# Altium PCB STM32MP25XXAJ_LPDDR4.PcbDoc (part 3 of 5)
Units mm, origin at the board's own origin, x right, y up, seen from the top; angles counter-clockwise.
Board outline 172 x 137 mm, 4 copper layers (Top Layer, Signal Layer 1, Signal Layer 2, Bottom Layer), stack 1.614 mm thick; 188 components, 294 nets, 1141 pads, 872 vias.
Unrouted connection lines stored in the file: 13.

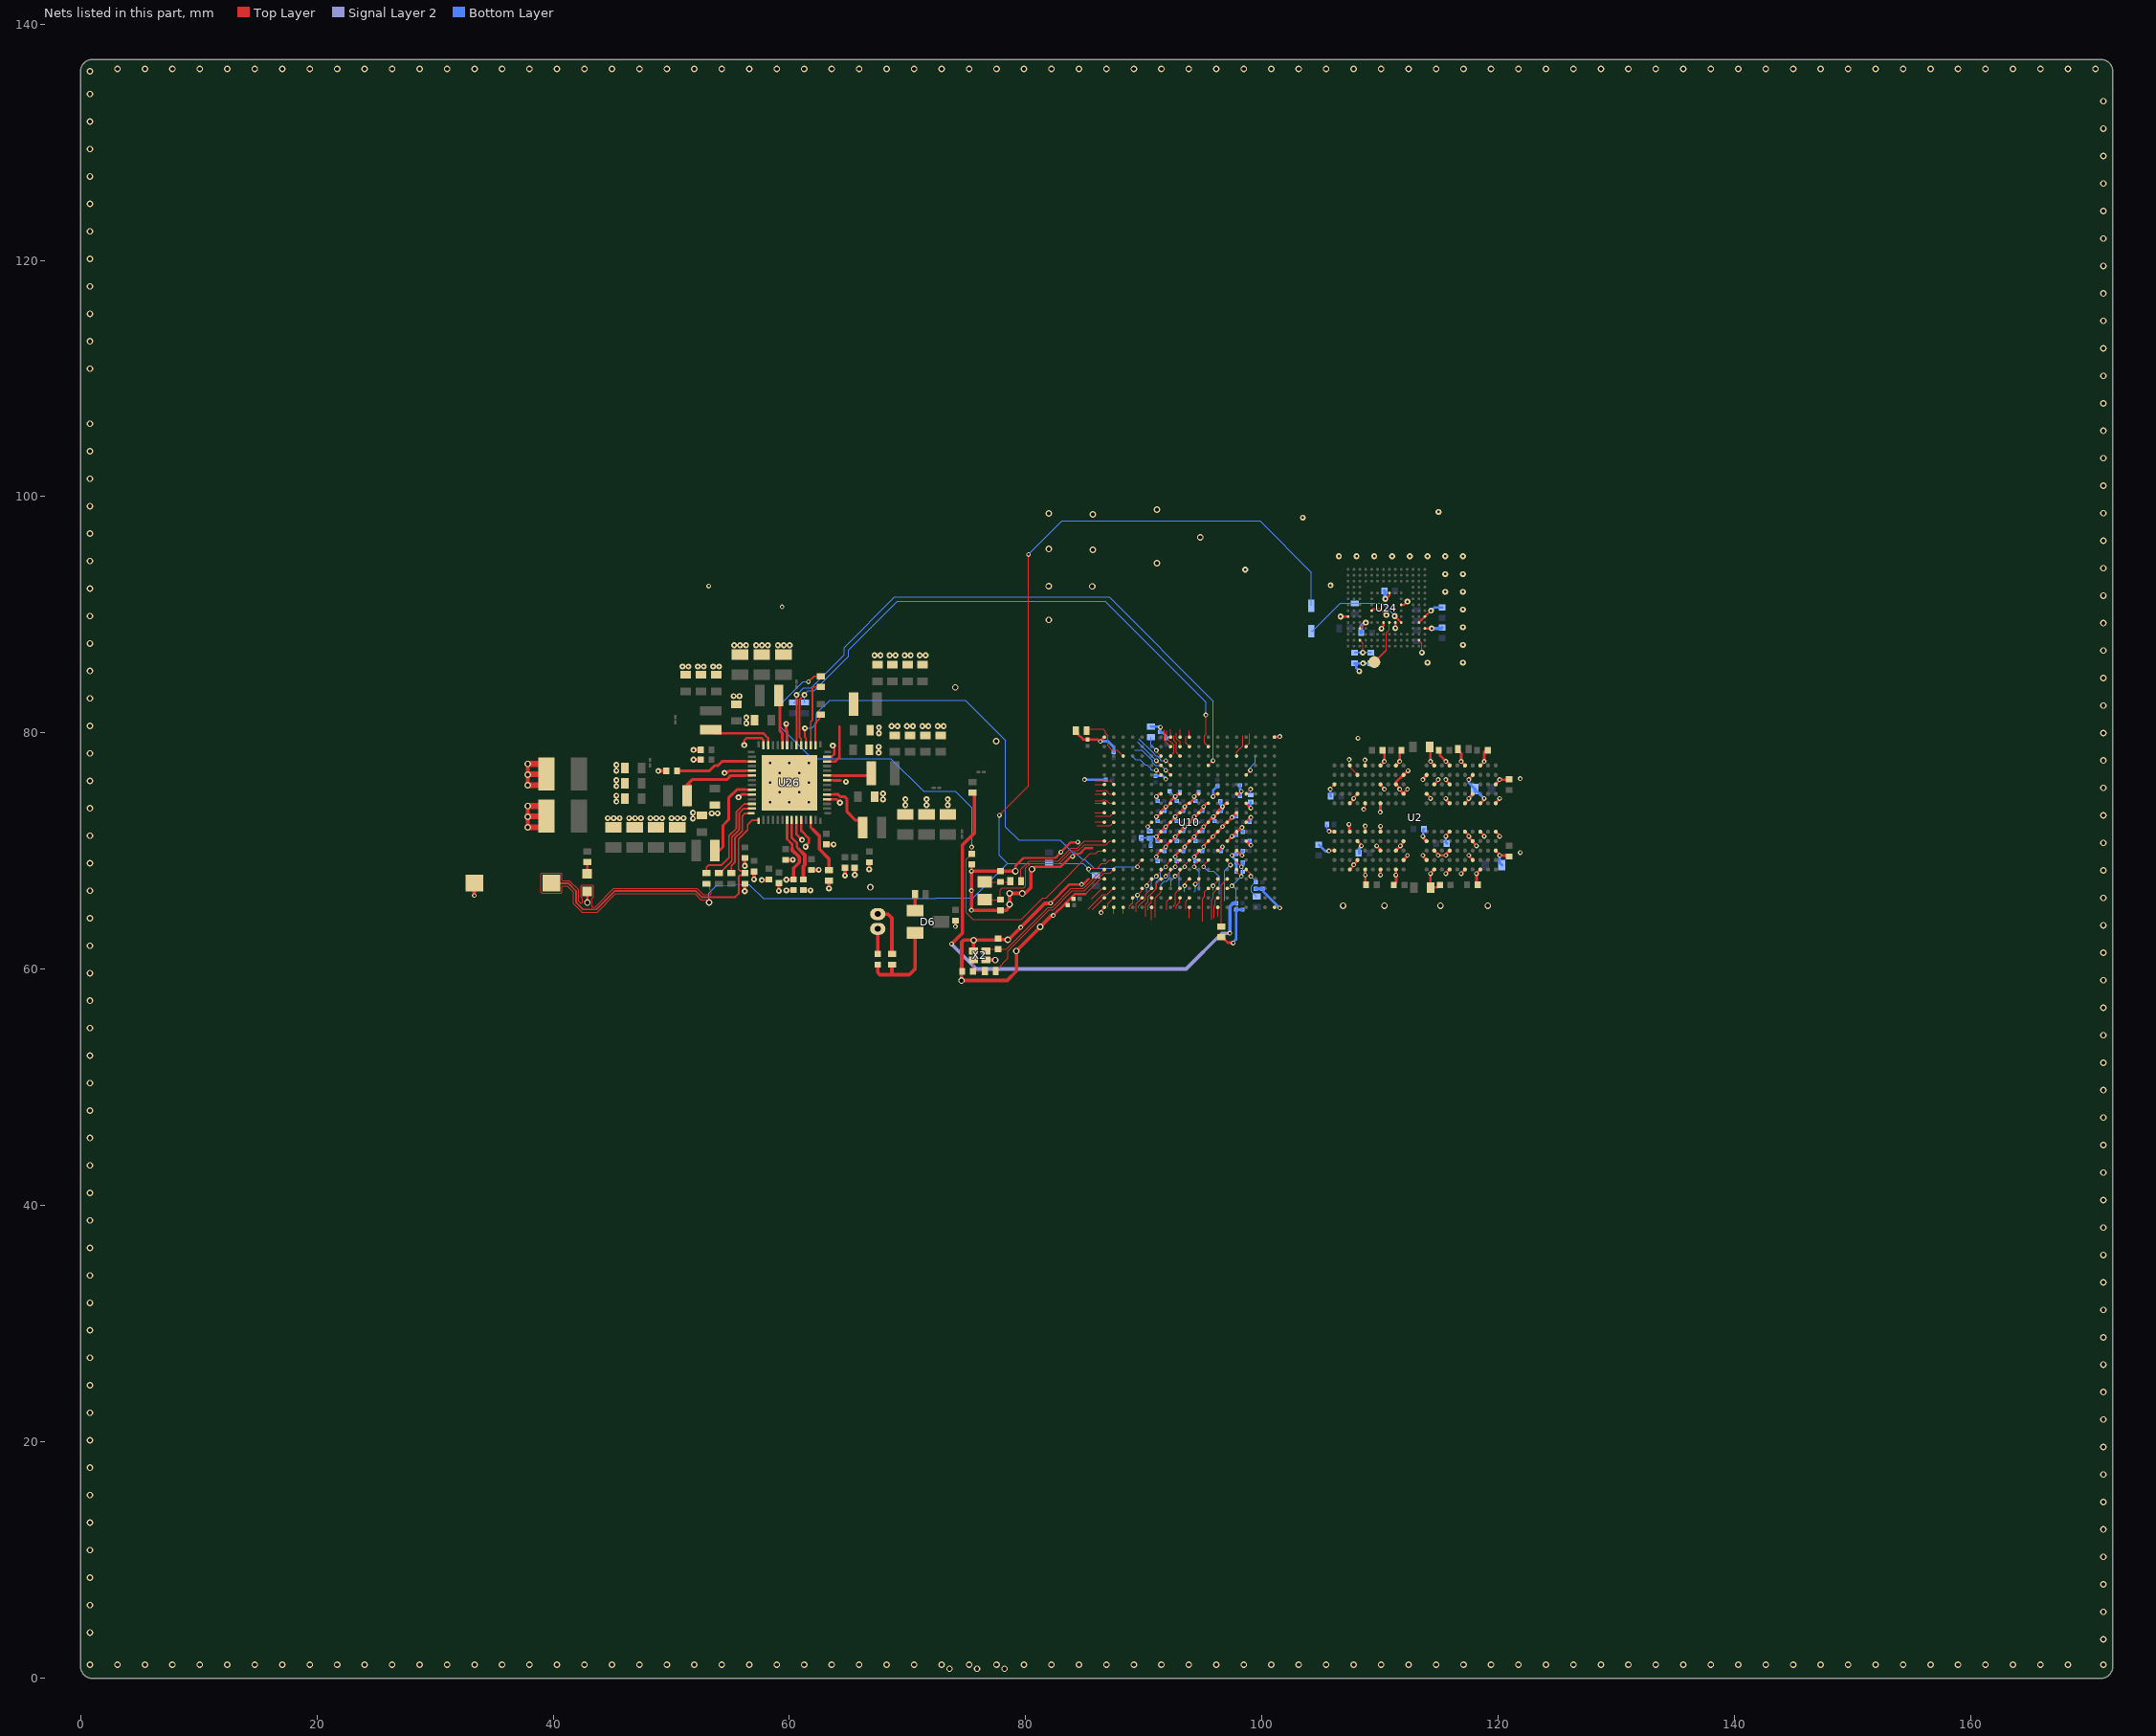
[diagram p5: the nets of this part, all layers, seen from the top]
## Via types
v1: diameter 0.55, hole 0.35, Top Layer to Bottom Layer, 349 vias
v2: diameter 0.4, hole 0.2, Top Layer to Bottom Layer, tented both sides, 257 vias
v3: diameter 0.5, hole 0.2, Top Layer to Bottom Layer, 189 vias
v4: diameter 0.4, hole 0.2, Top Layer to Bottom Layer, 77 vias

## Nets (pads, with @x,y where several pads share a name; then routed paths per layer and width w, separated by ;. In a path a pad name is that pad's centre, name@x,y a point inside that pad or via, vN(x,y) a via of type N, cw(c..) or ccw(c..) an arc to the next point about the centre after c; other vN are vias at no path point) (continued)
GND: B2.1 C18.2 C19.1 C20.1 C21.1 C22.1 C23.1 C24.1 C26.1 C27.1 C28.1 C29.1 C30.1 C32.1 C33.1 C34.1 C35.1 C36.1 C37.1 C38.1 C39.1 C40.1 C41.1 C42.2 C43.1 C50.1 C51.1 C52.1 C53.2 C54.2 C55.2 C56.2 C57.2 C58.2 C59.2 C60.2 C61.2 C62.1 C63.1 C64.1 C65.1 C66.1 C67.1 C68.1 C79.1 C81.2 C86.2 C87.1 C90.1 C91.2 C92.2 C141.2 C142.2 C143.1 C152.1 C153.1 C154.1 C155.1 C156.1 C157.1 C159.1 C161.1 C163.1 C164.2 C165.1 C166.1 C167.1 C168.1 C169.1 C171.1 C173.2 C174.2 C175.1 C176.1 C177.1 C180.1 C182.1 C183.1 C184.1 C186.1 C187.1 C188.1 C189.1 C190.2 C191.2 C192.1 C193.1 C195.1 C196.1 C199.1 C200.1 C201.1 C202.1 C204.1 C206.1 C207.1 C208.2 C209.1 C210.1 C217.2 C267.1 C342.1 C344.1 C352.1 C353.1 C354.1 C355.1 C356.1 C357.1 C360.2 C372.1 C377.1 C378.1 C380.1 C381.1 C382.1 C383.1 C384.1 C386.1 C387.2 C388.1 C389.2 C390.1 C393.1 C399.2 C400.1 C402.1 C404.1 C406.1 C407.1 C408.1 C409.1 C417.1 C478.1 C479.1 C481.1 LD11.2 R26.1 R57.1 R112.1 R161.2 R162.2 R196.1 U2.A3 U2.A10 U2.AB3 U2.AB5 U2.AB8 U2.AB10 U2.C1 U2.C5 U2.C8 U2.C12 U2.D2 U2.D4 U2.D9 U2.D11 U2.E1 U2.E5 U2.E8 U2.E12 U2.G1 U2.G3 U2.G5 U2.G8 U2.G10 U2.G12 U2.J1 U2.J3 U2.J10 U2.J12 U2.K2 U2.K4 U2.K9 U2.K11 U2.N2 U2.N4 U2.N9 U2.N11 U2.P1 U2.P3 U2.P10 U2.P12 U2.T1 U2.T3 U2.T5 U2.T8 U2.T10 U2.T12 U2.V1 U2.V5 U2.V8 U2.V12 U2.W2 U2.W4 U2.W9 U2.W11 U2.Y1 U2.Y5 U2.Y8 U2.Y12 U10.A1 U10.A19 U10.G7 U10.G9 U10.G11 U10.G13 U10.G15 U10.H8 U10.H10 U10.H12 U10.H14 U10.H16 U10.J7 U10.J9 U10.J11 U10.J13 U10.J15 U10.K8 U10.K10 U10.K12 U10.K14 U10.K16 U10.L7 U10.L9 U10.L11 U10.L13 U10.L15 U10.M7 U10.M8 U10.M10 U10.M12 U10.M14 U10.M16 U10.N7 U10.N9 U10.N11 U10.N13 U10.N15 U10.T1 U10.W1 U10.W19 U24.A6 U24.C4 U24.E7 U24.G5 U24.H10 U24.J5 U24.K8 U24.N2 U24.N5 U24.P4 U24.P6 U26.9 U26.10 U26.18 U26.22 U26.27 U26.36 U26.41 U26.47 U26.52 U26.57 X2.2 X2.4 | length 247.7
  Top Layer w0.09: U10.W19@101.05,65.25 101.45,65.25 v4@101.5,65.2 ; v4@105.778,75.296 106.157,75.675 U2.A10@106.175,75.675 ; v4(107.375,77.75) 107.375,77.375 U2.C12@107.45,77.3 ; U2.C12@107.421,77.247 107.474,77.194 107.474,77.051 U2.D11@108.075,76.45 ; v4@108.6,73.525 108.725,73.65 U2.E8@108.725,74.05 ; v4@108.7,77.75 108.725,77.725 U2.E12@108.725,77.25 ; U24.N2@113.275,87.85 113.525,87.6 v3(113.525,86.8)
  Top Layer w0.1: v3@44.624,72.799 v3@44.625,72.8 ; X2.2@75.547,61.575 X2.2@75.548,61.576 ; v1@75.573,62.448 v1(75.587,62.462) v1@75.6,62.475 ; 85.068,66.382 86.336,67.65 U10.T1@86.65,67.65
  Top Layer w0.11: v4@86.291,64.884 U10.W1@86.65,65.244
  Top Layer w0.18: v3(106.65,89.85) U24.A6@107.275,89.85 ; U24.C4@108.275,88.85 108.725,89.3 108.735,89.3 v3(108.775,89.34) ; U24.E7@109.275,90.35 109.283,90.35 109.416,90.483 110.028,90.483 110.516,89.995 v3(110.525,89.995) ; v3(110.1,88.825) 110.1,88.913 110.275,89.088 U24.G5@110.275,89.35 ; v3@110.425,91.275 110.775,91.625 U24.H10@110.775,91.85 ; v3(111.275,88.875) 111.285,88.885 111.285,89.34 U24.J5@111.275,89.35 ; U24.K8@111.775,90.85 112.025,90.85 v3(112.3,91.125) ; U24.N5@113.275,89.35 U24.P6@113.775,89.85 114.275,90.35 v3(114.3,90.35) ; U24.P4@113.775,88.85 v3(114.35,88.85)
  Top Layer w0.2: v1(42.887,65.648) LD11.2@42.887,66.577 ; U26.27@63.17,78 63.579,78 63.77,78.191 63.77,78.91 v3@63.816,78.956 ; v3(63.67,78.93) v3@63.727,78.873 ; C87.1@74.05,64.125 74.05,63.634 v2(74.051,63.633) ; v2(75.402,68.305) 75.416,68.319 C33.1@75.416,68.915 ; v1(79.125,68.3) 79.125,68.75 79.8,69.425 82.507,69.425 82.975,69.893 v2(82.975,69.925) 83.8,70.75 v4@84.456,70.75 ; v1(80.525,68.475) 80.599,68.475 80.818,68.693 82.956,68.693 83.784,69.522 v2@83.934,69.522 ; v2(82.1,65.6) 83.683,67.182 84.711,67.182 84.763,67.234 84.911,67.234 85.319,67.643 ; v2(82.325,64.55) 83.363,65.587 ; C67.1@83.55,65.425 83.525,65.425 83.363,65.587 ; v2@83.975,69.575 84.19,69.79 84.568,69.79 85.031,70.253 85.603,70.253 ; C406.1@84.025,65.975 83.9,66.1 C406.1@83.9,66.125 ; 85.068,66.382 85.065,66.385 84.784,66.385 84.781,66.382 84.158,66.382 C406.1@83.9,66.125 ; v4(91.05,69.525) 91.05,69.65 U10.N7@91.45,70.05 ; U10.N7@91.445,70.05 U10.N7@91.45,70.05 ; v2@91.85,70.438 91.462,70.05 U10.N7@91.45,70.05 ; v2@91.851,70.438 v2@91.863,70.438 ; v2(92.65,69.525) 92.709,69.584 92.709,69.709 U10.N9@93.05,70.05 93.125,70.05 v2(93.45,70.375) ; U2.G10@110.025,75.65 110.025,75.61 110.1,75.535 110.1,75.531 110.35,75.281 v2(110.35,75.25) ; 83.363,65.587 C406.1@83.9,66.125
  Top Layer w0.21: v3(56.175,78.975) 56.175,79.375 56.38,79.58 57.609,79.58 57.8,79.389 U26.41@57.8,78.97 ; 56.275,74.8 U26.52@56.83,74.8 ; 56.275,76.8 U26.47@56.83,76.8 ; U26.36@59.8,78.97 59.8,79.525 ; U26.9@60.6,72.63 60.6,71.42 v3(61.068,70.952) ; U26.10@61,72.63 61,71.734 61.635,71.099 61.635,70.72 61.37,70.456 v3(61.37,70.377) ; U26.18@63.17,74.4 63.972,74.4 v3(64.272,74.1) ; U26.22@63.17,76 63.725,76
  Top Layer w0.22: R162.2@84.25,80.2 84.395,80.055 84.395,79.914 84.854,79.455 85.22,79.455 C353.1@85.225,79.45 86.097,79.45 86.262,79.285 v4(86.31,79.285) 86.31,79.298 86.63,79.618 86.63,79.648 U10.A1@86.625,79.653 ; v2(91.05,71.225) 91.05,71.25 U10.L7@91.45,71.65 91.45,71.675 v2(91.85,72.075) ; v2(91.05,72.925) 91.084,72.959 91.164,72.959 U10.J7@91.45,73.245 ; v2@91.052,74.625 91.257,74.831 91.431,74.831 U10.G7@91.45,74.85 ; v2@91.07,71.146 91.112,71.146 91.393,70.865 91.393,70.85 U10.M7@91.445,70.85 ; U10.J7@91.45,73.25 91.465,73.265 91.465,73.404 v2@91.836,73.775 ; v2(91.85,70.375) 91.85,70.438 91.85,70.45 U10.M8@92.25,70.85 ; v2(91.85,73.775) 91.884,73.809 91.999,73.809 92.239,74.05 U10.H8@92.25,74.05 92.25,74.225 v2(92.65,74.625) 92.65,74.645 92.841,74.836 93.031,74.836 U10.G9@93.045,74.85 ; v2@91.875,72.075 U10.K8@92.25,72.45 92.65,72.85 v2(92.65,72.925) 92.65,72.939 92.894,73.183 92.926,73.183 92.993,73.25 U10.J9@93.05,73.25 93.425,73.625 v2@93.425,73.775 ; U10.M8@92.245,70.85 U10.M8@92.25,70.85 ; v4(92.65,71.225) 93.05,71.625 U10.L9@93.05,71.65 ; v4@92.698,71.18 92.637,71.18 92.307,70.85 U10.M8@92.25,70.85 ; U10.L9@93.045,71.65 93.348,71.954 93.441,71.954 93.441,72.046 U10.J11@94.647,73.253 ; v2(93.45,70.375) 93.45,70.45 U10.M10@93.85,70.85 93.875,70.85 v2(94.25,71.225) ; v2(93.45,73.775) 93.45,73.787 93.676,74.013 93.813,74.013 U10.H10@93.85,74.05 94.25,74.45 v2(94.25,74.625) 94.457,74.832 94.626,74.832 U10.G11@94.645,74.85 ; v2@94.225,69.525 94.65,69.95 U10.N11@94.65,70.05 ; v2@94.25,71.255 94.645,71.65 U10.L11@94.65,71.65 ; U10.J11@94.625,73.25 95.05,73.675 v2(95.05,73.775) 95.05,73.793 95.267,74.01 95.41,74.01 U10.H12@95.45,74.05 ; U10.L11@94.675,71.7 v4(95.05,72.075) ; v4(95.05,70.375) 95.084,70.409 95.084,70.484 U10.M12@95.45,70.85 95.825,71.225 v4(95.85,71.225) 95.85,71.253 U10.L13@96.247,71.65 ; v4@95.075,72.075 U10.K12@95.45,72.45 95.465,72.465 95.465,72.535 95.845,72.915 95.909,72.915 U10.J13@96.245,73.25 ; v2(95.85,74.625) 95.85,74.638 96.05,74.838 96.238,74.838 U10.G13@96.25,74.85 ; U10.N13@96.246,70.05 96.325,70.05 v2(96.65,70.375) ; U10.L13@96.25,71.661 v4@96.65,72.061 ; U10.J13@96.25,73.25 96.25,73.375 v2(96.65,73.775) ; R196.1@96.55,62.725 96.645,62.725 97.111,62.259 97.516,62.259 v4(97.55,62.225) ; v4(96.65,72.075) 97.025,72.45 U10.K14@97.05,72.45 ; v2@96.65,73.781 96.878,74.01 97.01,74.01 U10.H14@97.05,74.05 ; U10.M14@97.052,70.85 v2@97.45,71.248 ; U10.K14@97.052,72.45 v4@97.45,72.848 ; v4@97.45,72.854 U10.J15@97.846,73.25 ; v2@97.484,71.284 U10.L15@97.85,71.65 97.9,71.65 v2@98.25,72 ; U10.N15@97.835,70.035 U10.N15@97.85,70.05 ; U10.N15@97.85,70.049 v4@98.249,69.65 ; U10.G15@97.85,74.85 98.04,74.85 v2(98.25,75.06) ; U10.K16@98.65,72.45 v2(99.05,72.85) ; U10.H16@98.65,74.05 v2(99.05,73.65) ; U10.M16@98.652,70.85 99.002,70.5 v2(99.05,70.5) ; U10.A19@101.05,79.65 101.065,79.665 101.53,79.665 v4@101.55,79.685 ; v2(105.65,70.015) 105.699,70.015 105.734,70.05 U2.A3@106.125,70.05 ; v2(107.345,72.275) 107.375,72.245 107.375,71.861 107.4,71.836 107.4,71.675 U2.C5@107.425,71.65 ; U2.C1@107.425,68.45 107.75,68.776 v2(107.75,68.85) 108.075,69.175 U2.D2@108.075,69.25 ; U2.C8@107.425,74.05 107.745,74.37 107.75,74.37 107.784,74.405 107.784,74.56 U2.D9@108.075,74.85 ; v2@107.725,68.825 v2@107.725,68.901 ; U2.D4@108.075,70.85 108.365,70.56 108.365,70.47 v2@108.4,70.435 ; C66.1@108.725,67.295 C66.1@108.85,67.17 ; v2@108.725,67.95 U2.E1@108.725,68.45 ; U2.E5@108.725,71.65 v2(108.725,72.125) v2@108.725,72.135 ; v2(108.736,67.975) 108.736,67.314 C66.1@108.9,67.15 ; v2(109.7,70.45) 109.96,70.19 109.96,70.15 110.025,70.085 U2.G3@110.025,70.05 ; v2@110.025,67.96 v2(110.025,67.97) U2.G1@110.025,68.45 ; U2.G5@110.025,71.65 v4@110.025,72.075 ; U2.G12@110.025,77.25 110.35,77.575 v2(110.35,77.6) 110.35,78.251 110.337,78.264 110.337,78.405 C64.1@110.192,78.55 ; C54.2@111.15,67.135 111.15,67.16 111.353,67.364 111.353,67.941 v2(111.325,67.97) U2.J1@111.325,68.45 ; U2.J3@111.325,70.05 111.7,70.426 v2(111.7,70.45) 111.7,70.478 111.95,70.728 U2.K4@111.95,70.825 ; U2.J10@111.325,75.645 111.659,75.31 v2@111.659,75.295 ; U2.J10@111.325,75.65 111.349,75.675 111.349,75.849 111.95,76.45 U2.K11@111.975,76.45 112.324,76.8 v2(112.35,76.8) ; U2.J12@111.325,77.25 111.33,77.25 v2@111.65,77.57 ; v2(111.65,77.6) 111.65,78.251 111.655,78.256 111.655,78.405 C52.1@111.8,78.55 ; v2@111.694,75.276 111.684,75.266 111.684,75.164 U2.K9@111.975,74.873 ; U2.K2@111.975,69.25 111.98,69.25 v2@112.3,69.57 ; U2.K9@111.975,74.85 U2.K9@111.975,74.873 ; v2(112.3,75.25) 112.3,75.208 111.975,74.883 U2.K9@111.975,74.873 ; v2(113.6,69.65) 113.634,69.616 113.634,69.561 U2.N2@113.925,69.271 ; v2@113.6,71.17 113.92,70.85 U2.N4@113.925,70.85 ; v2@113.6,76.12 113.925,76.445 U2.N11@113.925,76.45 ; U2.N9@113.925,74.85 114.215,74.56 114.215,74.485 v2(114.25,74.45) ; C62.1@114.045,78.625 114.2,78.78 114.25,78.73 v2(114.25,77.6) 114.25,77.575 U2.P12@114.575,77.25 ; C63.1@114.25,66.92 v2(114.25,68.1) 114.25,68.12 114.575,68.445 U2.P1@114.575,68.45 ; C63.1@114.25,66.938 114.853,66.938 114.88,66.965 114.905,66.965 115.05,67.11 C267.1@115.05,67.135 ; U2.P3@114.575,70.035 114.865,69.745 114.865,69.685 v2(114.9,69.65) v2(115.55,69.65) ; U2.P10@114.575,75.65 114.895,75.97 v2@114.9,75.97 ; C65.1@114.975,78.56 115.063,78.472 115.063,78.087 v2(115.55,77.6) 115.875,77.275 U2.T12@115.875,77.25 ; v2@115.55,68.12 115.875,68.445 U2.T1@115.875,68.45 ; v2@115.55,71.32 115.875,71.645 U2.T5@115.875,71.65 ; v2(115.55,74.45) 115.584,74.416 115.584,74.341 U2.T8@115.875,74.05 ; v2@115.55,75.97 115.87,75.65 U2.T10@115.875,75.65 ; v2@115.575,69.625 v2(115.55,69.65) ; U2.T3@115.875,70.05 115.875,70.024 115.584,69.734 115.584,69.685 v2(115.55,69.65) ; R26.1@116.575,78.635 116.575,78.54 R26.1@116.72,78.395 ; R26.1@116.721,78.395 116.85,78.266 v2(116.85,77.6) ; v2@116.85,68.12 117.175,68.445 U2.V1@117.175,68.45 ; v2@116.85,77.575 U2.V12@117.175,77.25 ; U2.V5@117.175,71.65 117.465,71.36 117.465,71.205 117.5,71.17 117.505,71.17 U2.W4@117.825,70.85 117.825,70.815 117.89,70.75 117.89,70.71 v2(118.15,70.45) ; U2.V8@117.175,74.05 117.465,74.341 117.465,74.416 v2(117.5,74.45) 117.5,74.525 U2.W9@117.825,74.85 ; v2(117.5,69.65) 117.5,69.603 117.825,69.278 U2.W2@117.825,69.25 ; v2@117.5,76.12 117.825,76.445 U2.W11@117.825,76.45 ; C55.2@118.25,67.15 118.15,67.25 v2(118.15,68.1) 118.15,68.12 118.475,68.445 U2.Y1@118.475,68.45 ; U2.Y5@118.475,71.65 118.475,71.645 v2@118.8,71.32 ; U2.Y8@118.475,74.05 118.765,74.341 118.765,74.416 v2(118.8,74.45) ; U2.Y12@118.475,77.25 118.48,77.25 v2@118.8,77.57 ; v2(118.8,77.6) 118.8,78.231 118.805,78.236 118.805,78.385 C53.2@118.95,78.53 ; U2.AB3@119.775,70.034 120.065,69.744 v2@120.065,69.685 ; U2.AB5@119.775,71.65 120.1,71.325 v2@120.1,71.32 ; U2.AB8@119.775,74.05 119.775,74.073 120.065,74.363 120.065,74.405 v2@120.05,74.42 ; U2.AB10@119.775,75.65 119.775,75.685 119.84,75.75 119.84,75.761 v2@120.128,76.05 ; v2(120.1,76.05) v2@120.128,76.05 ; v2@120.114,69.636 120.798,69.636 C57.2@120.9,69.534 ; v2@120.148,76.07 v2@120.128,76.05 ; C56.2@120.9,76.07 120.88,76.05 v2@120.128,76.05
  Top Layer w0.25: v3(54.508,76.625) 54.556,76.673 54.757,76.673 54.884,76.8 56.275,76.8 ; v3(55.687,74.563) 55.721,74.563 55.959,74.8 56.275,74.8 ; v3(59.725,80.775) 59.725,80.214 59.8,80.139 59.8,79.525 ; 63.725,76 64.33,76 ; v3@64.257,74.1 v3(64.272,74.1)
  Top Layer w0.28: v2(110,73.3) 110.012,73.312 110.012,74.038 U2.G8@110.025,74.05
  Top Layer w0.3: v2(33.319,66.245) 33.324,66.25 33.324,67.279 B2.1@33.34,67.295 ; v1(37.848,72.014) v1(37.848,72.914) v1(37.848,73.814) ; v1(37.848,75.576) v1(37.848,76.476) v1(37.848,77.376) ; v3(48.895,76.79) C43.1@49.555,76.79 ; v3(51.885,77.75) C40.1@52.495,77.75 ; v3(51.885,78.575) C39.1@52.495,78.575 ; v3@56.225,68.81 C217.2@56.225,69.42 ; v3@56.227,66.58 C155.1@56.227,67.185 ; v3(57,67.61) C154.1@57,68.215 ; v3(57.665,67.55) C142.2@58.275,67.55 ; v3@59.1,66.69 C141.2@59.1,67.3 ; C153.1@59.675,69.27 v3(60.285,69.27) ; v3(59.74,66.68) C91.2@60.35,66.68 ; C208.2@61.175,66.68 v3(61.785,66.68) ; C209.1@61.85,68.42 v3(62.485,68.42) ; C156.1@63.125,70.57 v3(63.735,70.57) ; v3(63.35,66.84) R57.1@63.35,67.5 ; v3(64.7,67.93) C189.1@64.7,68.59 ; v3(65.525,67.99) C188.1@65.525,68.59 C188.1@65.525,68.65 ; v3@66.75,68.465 66.747,68.467 66.747,69.063 C190.2@66.75,69.065 ; C92.2@74.563,59.875 74.563,59.087 74.588,59.063 78.438,59.063 79.225,59.85 79.225,61.525 v1(79.2,61.55) 81.225,63.575 v1(81.225,63.6) 82.156,64.531 82.306,64.531 v2(82.325,64.55) ; C92.2@74.625,59.825 74.576,59.874 74.576,62.299 74.752,62.475 75.6,62.475 76,62.475 76.013,62.488 76.663,62.488 76.675,62.475 77.5,62.475 77.625,62.6 C90.1@77.65,62.6 77.736,62.514 v1@78.475,62.514 ; v2(75.4,65) C86.2@77.85,65 ; 75.4,65.275 v2@75.4,66.65 ; v2@75.4,68.3 v2@75.402,68.3 ; v2(75.402,66.655) v2@75.402,68.3 ; v2(75.402,68.305) v2@75.402,68.3 ; X2.2@75.573,61.551 v1@75.573,62.448 ; X2.4@76.66,60.788 76.667,60.794 77.408,60.794 v1(77.415,60.788) ; C86.2@77.955,65.105 C86.2@77.85,65 ; v1(78.475,62.5) 78.525,62.5 v2(79.575,63.55) 81.606,65.581 v2@82.081,65.581 ; v1(79.125,68.3) C81.2@77.85,68.3 v2@75.402,68.3 ; v1(80.525,68.475) 80.43,68.38 80.43,66.905 79.993,66.468 79.748,66.468 v1(79.7,66.42) 79.695,66.425 v1(78.625,66.425) v1(78.625,65.5) 78.578,65.452 78.578,65.239 78.339,65 C86.2@77.85,65
  Top Layer w0.5: v1(37.848,72.014) 39.39,72.014 C18.2@39.437,72.061 ; v1(37.848,72.914) 37.862,72.914 37.909,72.961 C18.2@39.437,72.961 ; v1(37.848,73.814) C18.2@39.379,73.814 ; v1(37.848,75.576) 39.39,75.576 C42.2@39.437,75.623 ; v1(37.848,76.476) 37.862,76.476 37.909,76.523 C42.2@39.437,76.523 ; v1(37.848,77.376) C42.2@39.379,77.376
  Bottom Layer w0.1: C79.1@89.6,70.975 C79.1@89.689,70.975 ; C171.1@92.175,75.075 92.625,74.625 v2(92.65,74.625) ; v2@92.625,74.65 v2@92.7,74.65
  Bottom Layer w0.2: C79.1@89.75,71.125 90.5,71.125 90.525,71.1 C384.1@90.55,71.075 ; v4(91.05,69.525) 91.05,69.275 C399.2@91.175,69.15 ; v2(92.65,69.525) 92.65,69.25 C400.1@92.775,69.125 ; C404.1@100.025,66.825 100.1,66.75 100.1,66.595 v4@101.436,65.259 ; v3(108.225,85.225) 108.225,85.244 107.976,85.492 107.976,85.749 C182.1@107.825,85.9 v3(108.55,85.9) 109.175,85.9 C481.1@109.2,85.875 ; v3(114.3,90.35) 114.575,90.625 C478.1@115.225,90.625 C478.1@115.25,90.625
  Bottom Layer w0.22: v4@84.95,76.05 v4(84.975,76.05) C161.1@86.775,76.05 ; v4(86.31,79.285) 86.325,79.3 86.95,79.3 87.45,78.8 C356.1@87.45,78.4 ; C384.1@90.5,71.075 90.525,71.1 90.65,71.225 v2(91.05,71.225) ; C196.1@90.575,70.45 C384.1@90.575,71.1 ; R161.2@90.6,80.55 91.35,80.55 v4@91.4,80.5 ; v4@90.975,69.5 v4@91.025,69.5 ; C344.1@90.975,76.375 91.575,76.375 v4(91.85,76.1) ; v2@91.016,71.191 v2(91.05,71.225) ; v2(91.05,72.925) 91.05,72.7 C169.1@91.2,72.55 ; v2(91.05,74.625) 91.05,74.576 91.11,74.516 91.11,74.315 C166.1@91.175,74.25 ; C387.2@91.175,70.85 91.05,70.975 v2(91.05,71.225) ; v4(91.403,80.496) 91.403,80.047 91.415,80.035 91.596,80.035 91.835,79.796 91.835,79.615 C352.1@91.9,79.55 ; C393.1@91.725,70.025 91.85,70.15 v2(91.85,70.375) ; C378.1@91.725,71.7 91.85,71.825 v2(91.85,72.075) ; C173.2@91.725,73.425 91.85,73.55 v2(91.85,73.775) ; v4(92.65,71.225) 92.65,70.975 C380.1@92.775,70.85 ; v2(92.65,72.925) 92.65,72.675 C164.2@92.775,72.55 ; C390.1@92.775,74.275 92.65,74.4 v2(92.65,74.625) 92.675,74.625 92.7,74.65 C143.1@93.05,75 ; C192.1@93.325,70 93.45,70.125 v2(93.45,70.375) ; C372.1@93.325,71.7 93.45,71.825 v2(93.45,72.075) ; C167.1@93.325,73.4 93.45,73.525 v2(93.45,73.775) ; v2(94.25,69.525) 94.25,69.275 C402.1@94.375,69.15 C402.1@94.4,69.125 ; v2(94.25,71.225) 94.25,70.975 C382.1@94.375,70.85 ; v4(94.25,72.925) 94.25,72.675 C168.1@94.375,72.55 ; C360.2@94.375,74.25 94.25,74.375 v2(94.25,74.625) C342.1@94.625,75 ; C381.1@94.925,70 95.05,70.125 v4(95.05,70.375) ; C388.1@94.925,71.7 95.05,71.825 v4(95.05,72.075) ; C159.1@94.925,73.4 95.05,73.525 v2(95.05,73.775) ; v2(95.85,74.625) 95.85,75.125 C354.1@96.225,75.5 ; v2(95.875,72.925) 95.875,72.65 C163.1@95.975,72.55 ; C165.1@96.475,74.225 96.475,73.95 v2(96.65,73.775) 96.65,73.525 C174.2@96.525,73.4 ; C191.2@96.525,70.025 96.65,70.15 v2(96.65,70.375) ; v2(97.45,71.25) 97.7,71.25 C377.1@97.825,71.375 ; v4(97.45,72.85) 97.7,72.85 C201.1@97.825,72.975 C201.1@97.85,73 ; v4(97.55,62.225) 97.55,62.274 97.8,62.524 C407.1@97.8,65.05 C210.1@98.35,65.05 ; C386.1@97.802,69.752 97.76,69.71 97.559,69.71 97.499,69.65 v2(97.45,69.65) 97.484,69.616 97.484,69.529 97.76,69.253 97.76,69.115 C409.1@97.825,69.05 97.825,68.275 C417.1@97.85,68.25 ; C176.1@98.125,74.675 98.19,74.74 98.19,74.951 98.25,75.011 v2(98.25,75.06) 98.125,75.185 C357.1@98.125,75.575 C357.1@98.125,75.6 ; v4@98.25,69.65 98.25,69.9 C195.1@98.375,70.025 ; v2(98.3,72) 98.334,71.966 98.334,71.69 C383.1@98.399,71.625 ; C389.2@98.925,70.875 99.05,70.75 v2(99.05,70.5) ; C175.1@98.925,72.475 99.05,72.6 v2(99.05,72.85) ; R112.1@99.028,74.15 99.028,73.622 v2@99.05,73.6 ; C61.2@104.8,70.55 105.35,70 v2@105.65,70 ; v4(105.778,75.25) 105.778,74.672 C60.2@105.825,74.625 ; C59.2@108.225,69.8 108.225,70.276 v2(108.4,70.45) ; v2(113.6,71.25) 113.634,71.285 113.634,71.809 C68.1@113.7,71.875 ; v2(115.55,71.25) 115.55,70.75 C58.2@115.65,70.65 ; v2(117.5,74.45) 118,74.95 C51.1@118,75.225 ; v2(117.5,76.05) 117.5,75.775 C51.1@118,75.275 ; C51.1@117.975,75.225 C51.1@118,75.225 ; C51.1@118,75.3 C51.1@118,75.275 ; C51.1@118.025,75.25 C51.1@118,75.275 ; v2(118.8,74.45) 118.025,75.225 C51.1@118,75.225 ; v2(120.1,69.65) 120.1,69.025 C50.1@120.325,68.8 ; C51.1@118,75.225 C51.1@118,75.275
  Bottom Layer w0.28: C408.1@99.475,66.8 C404.1@100.025,66.8
  Bottom Layer w0.3: C180.1@108.4,88.475 108.4,89.049 108.643,89.292 108.727,89.292 v3(108.775,89.34) ; C177.1@110.35,92.025 110.425,91.95 v3(110.425,91.35) v3@110.425,91.275 ; v3(114.35,88.85) 115.15,88.85 C479.1@115.225,88.925
  other v1: 73.55,0.8 75.875,0.8 78.2,0.8 0.8,1.15 3.125,1.15 5.45,1.15 7.775,1.15 10.1,1.15 12.425,1.15 14.75,1.15 17.075,1.15 19.4,1.15 21.725,1.15 24.05,1.15 26.375,1.15 28.7,1.15 31.025,1.15 33.35,1.15 35.675,1.15 38,1.15 40.325,1.15 42.65,1.15 44.975,1.15 47.3,1.15 49.625,1.15 51.95,1.15 54.275,1.15 56.6,1.15 58.925,1.15 61.25,1.15 63.575,1.15 65.9,1.15 68.225,1.15 70.55,1.15 72.875,1.15 75.2,1.15 77.525,1.15 79.85,1.15 82.175,1.15 84.5,1.15 86.825,1.15 89.15,1.15 91.475,1.15 93.8,1.15 96.125,1.15 98.45,1.15 100.775,1.15 103.1,1.15 105.425,1.15 107.75,1.15 110.075,1.15 112.4,1.15 114.725,1.15 117.05,1.15 119.375,1.15 121.7,1.15 124.025,1.15 126.35,1.15 128.675,1.15 131,1.15 133.325,1.15 135.65,1.15 137.975,1.15 140.3,1.15 142.625,1.15 144.95,1.15 147.275,1.15 149.6,1.15 151.925,1.15 154.25,1.15 156.575,1.15 158.9,1.15 161.225,1.15 163.55,1.15 165.875,1.15 168.2,1.15 171.2,1.15 171.2,3.3 0.8,3.875 171.2,5.625 0.8,6.2 171.2,7.95 0.8,8.525 171.2,10.275 0.8,10.85 171.2,12.6 0.8,13.175 171.2,14.925 0.8,15.5 171.2,17.25 0.8,17.825 171.2,19.575 0.8,20.15 171.2,21.9 0.8,22.475 171.2,24.225 0.8,24.8 171.2,26.55 0.8,27.125 171.2,28.85 0.8,29.45 171.2,31.175 0.8,31.775 171.2,33.5 0.8,34.1 171.2,35.825 0.8,36.425 171.2,38.15 0.8,38.75 171.2,40.475 0.8,41.075 171.2,42.8 0.8,43.4 171.2,45.125 0.8,45.725 171.2,47.45 0.8,48.05 171.2,49.775 0.8,50.375 171.2,52.1 0.8,52.7 171.2,54.425 0.8,55.025 171.2,56.75 0.8,57.35 74.563,59.05 171.2,59.075 0.8,59.675 171.2,61.4 0.8,62 171.2,63.725 0.8,64.325 106.85,65.385 110.35,65.385 115.1,65.385 119.1,65.385 171.2,66.05 0.8,66.65 66.85,66.945 171.2,68.375 0.8,68.975 171.2,70.7 0.8,71.3 171.2,73.025 0.8,73.625 171.2,75.35 0.8,75.95 171.2,77.675 0.8,78.275 77.495,79.305 171.2,80 0.8,80.6 171.2,82.325 0.8,82.925 74.035,83.865 171.2,84.65 0.8,85.25 171.2,86.975 0.8,87.575 171.2,89.3 81.95,89.575 0.8,89.9 171.2,91.625 0.8,92.225 85.625,92.4 81.941,92.431 171.2,93.95 91.1,94.375 0.8,94.55 85.675,95.5 81.95,95.575 171.2,96.275 94.775,96.55 0.8,96.875 85.675,98.5 81.95,98.575 171.2,98.6 91.1,98.9 0.8,99.2 171.2,100.925 0.8,101.525 171.2,103.25 0.8,103.85 171.2,105.575 0.8,106.175 171.2,107.9 171.2,110.225 0.8,110.825 171.2,112.55 0.8,113.15 171.2,114.875 0.8,115.475 171.2,117.2 0.8,117.8 171.2,119.525 0.8,120.125 171.2,121.85 0.8,122.45 171.2,124.175 0.8,124.775 171.2,126.5 0.8,127.1 171.2,128.825 0.8,129.425 171.2,131.15 0.8,131.75 171.2,133.475 0.8,134.075 0.8,136 3.125,136.2 5.45,136.2 7.775,136.2 10.1,136.2 12.425,136.2 14.75,136.2 17.075,136.2 19.4,136.2 21.725,136.2 24.05,136.2 26.375,136.2 28.7,136.2 31.025,136.2 33.35,136.2 35.675,136.2 38,136.2 40.325,136.2 42.65,136.2 44.975,136.2 47.3,136.2 49.625,136.2 51.95,136.2 54.275,136.2 56.6,136.2 58.925,136.2 61.25,136.2 63.575,136.2 65.9,136.2 68.225,136.2 70.55,136.2 72.875,136.2 75.2,136.2 77.525,136.2 79.85,136.2 82.175,136.2 84.5,136.2 86.825,136.2 89.15,136.2 91.475,136.2 93.8,136.2 96.125,136.2 98.45,136.2 100.775,136.2 103.1,136.2 105.425,136.2 107.75,136.2 110.075,136.2 112.4,136.2 114.725,136.2 117.05,136.2 119.375,136.2 121.7,136.2 124.025,136.2 126.35,136.2 128.675,136.2 131,136.2 133.325,136.2 135.65,136.2 137.975,136.2 140.3,136.2 142.625,136.2 144.95,136.2 147.275,136.2 149.6,136.2 151.925,136.2 154.25,136.2 156.575,136.2 158.9,136.2 161.225,136.2 163.55,136.2 165.875,136.2 168.2,136.2 170.525,136.2
  other v2: 115.55,68.1 116.85,68.1 83.972,69.56 112.3,69.65 121.85,69.885 117.5,71.25 118.8,71.25 120.1,71.25 107.75,74.45 120.1,74.45 111.65,75.25 113.6,76.05 114.9,76.05 115.55,76.05 121.85,76.135 108.125,79.55 59.375,90.675 53.175,92.437
  other v3: 56.222,66.61 59.1,66.64 66.745,68.46 56.225,68.76 51.825,72.75 44.624,72.798 45.125,72.798 45.626,72.798 46.424,72.798 46.925,72.798 47.426,72.798 48.224,72.798 48.725,72.798 49.226,72.798 50.024,72.798 50.525,72.798 51.026,72.798 53.424,73.202 53.925,73.202 51.825,73.25 69.804,73.9 71.604,73.9 73.404,73.9 58.35,74.15 60,74.15 61.65,74.15 45.35,74.2 67.92,74.375 69.804,74.401 71.604,74.401 73.404,74.401 45.35,74.7 67.92,74.875 59.175,74.975 60.825,74.975 45.35,75.5 58.35,75.8 60,75.8 61.65,75.8 64.78,75.875 45.35,76 59.175,76.625 60.825,76.625 45.35,76.8 45.35,77.3 58.35,77.45 60,77.45 61.65,77.45 67.55,78.325 67.55,78.825 67.575,79.975 67.575,80.475 68.65,80.575 69.15,80.575 69.95,80.575 70.45,80.575 71.25,80.575 71.75,80.575 72.55,80.575 73.05,80.575 56.35,80.823 56.35,81.323 55.275,83.123 55.776,83.123 50.95,85.623 51.451,85.623 52.25,85.623 52.751,85.623 53.55,85.623 54.051,85.623 114,85.95 117,85.95 67.2,86.575 67.7,86.575 68.475,86.575 68.975,86.575 69.75,86.575 70.25,86.575 71.025,86.575 71.525,86.575 55.324,87.425 55.825,87.425 56.326,87.425 57.174,87.425 57.675,87.425 58.176,87.425 59.024,87.425 59.525,87.425 60.026,87.425 117,87.45 117,88.95 117,90.45 115.5,91.95 117,91.95 105.8,92.5 115.5,93.45 117,93.45 98.575,93.825 106.5,94.95 108,94.95 109.5,94.95 111,94.95 112.5,94.95 114,94.95 115.5,94.95 117,94.95 103.45,98.225 114.936,98.709
  other v4: 86.375,64.8 101.5,65.192 84.725,67.196 98.3,69.65 84.405,70.777 110.025,72.1 108.6,73.55 108.7,77.725 101.5,79.7
HSE_IN: C90.2 U10.R1 X2.1 | length 12.9
  Top Layer w0.1: X2.1@76.623,61.551 76.772,61.7 C90.2@77.65,61.7 78.35,61.7 81.9,65.25 82.245,65.25 83.841,66.846 84.876,66.846 86.18,68.15 86.345,68.15 U10.R1@86.645,68.45
HSE_OUT: R3.2 U10.R2 | length 14.1
  Top Layer w0.1: R3.2@77.375,59.725 77.58,59.93 77.58,60.027 78.48,60.927 ; 78.483,60.924 78.483,61.55 81.983,65.05 82.328,65.05 83.924,66.646 84.959,66.646 86.255,67.942 86.42,67.942 86.625,68.147 87.172,68.147 87.45,68.425 U10.R2@87.45,68.45
I2C7.SCL: R261.1 U10.B12 U26.33 | length 50.2
  Top Layer w0.1: v4(95.25,81.525) 95.25,79.874 95.15,79.774 95.15,79.15 U10.B12@95.45,78.85
  Top Layer w0.15: U26.33@61,78.97 61,79.5 60.85,79.65 60.85,82.813 v3(61.262,83.225)
  Bottom Layer w0.1: v3@61.268,83.22 61.268,82.625 R261.1@61.305,82.588 ; v3@61.268,83.23 61.268,83.265 61.578,83.575 62.089,83.575 65.019,86.505 65.019,87.016 69.143,91.14 86.723,91.14 95.25,82.613 v4(95.25,81.525)
I2C7.SDA: R260.1 U10.D12 U26.34 | length 53.4
  Top Layer w0.09: U10.D12@95.445,77.25 95.445,77.296 95.748,77.599 v2@95.748,77.645
  Top Layer w0.15: U26.34@60.6,78.97 v3(60.6,83.225)
  Bottom Layer w0.09: v2(95.85,77.65) 95.873,77.673 95.873,82.702
  Bottom Layer w0.1: R260.1@60.33,82.58 60.42,82.58 60.6,82.76 v3(60.6,83.225) ; v3@60.613,83.225 61.202,83.814 61.833,83.814 64.619,86.6 64.619,87.231 68.901,91.513 87.062,91.513 95.873,82.702
JTCK_SWCLK: U10.V1 | length 1.4
  Top Layer w0.09: 85.661,65.083 86.627,66.05 U10.V1@86.65,66.05
JTDI: U10.W2 | length 0.5
  Top Layer w0.09: 87.45,64.7 U10.W2@87.45,65.25
JTDO_SWDO: U10.U1 | length 1.4
  Top Layer w0.1: 85.578,65.975 86.421,66.818 86.609,66.818 U10.U1@86.614,66.814
JTMS_SWDIO: U10.V2 | length 1
  Top Layer w0.09: 86.945,65.225 86.945,65.545 U10.V2@87.45,66.05
LVDS1_D0N: U10.F2 | length 1.7
  Top Layer w0.09: 85.85,75.947 87.153,75.947 U10.F2@87.45,75.65
LVDS1_D0P: U10.F1 | length 0.8
  Top Layer w0.09: 85.875,75.65 U10.F1@86.65,75.65
LVDS1_D1N: U10.G2 | length 1.7
  Top Layer w0.09: 85.922,75.098 86.481,75.098 86.528,75.145 86.772,75.145 87.07,74.848 U10.G2@87.448,74.848
LVDS1_D1P: U10.G1 | length 0.8
  Top Layer w0.09: 85.875,74.85 U10.G1@86.65,74.85
LVDS1_D2N: U10.H2 | length 1.7
  Top Layer w0.09: 85.869,74.274 86.457,74.274 86.538,74.355 86.762,74.355 87.058,74.059 87.441,74.059 U10.H2@87.45,74.05
LVDS1_D2P: U10.H1 | length 0.8
  Top Layer w0.09: 85.875,74.05 U10.H1@86.65,74.05
LVDS1_D3N: U10.K2 | length 1.6
  Top Layer w0.09: 86.018,72.155 87.155,72.155 U10.K2@87.45,72.45
LVDS1_D3P: U10.K1 | length 0.8
  Top Layer w0.09: 85.875,72.467 86.633,72.467 U10.K1@86.65,72.45
LVDS1_D4N: U10.J2 | length 1.7
  Top Layer w0.09: 85.896,72.954 87.154,72.954 U10.J2@87.45,73.25
LVDS1_D4P: U10.J1 | length 0.8
  Top Layer w0.09: 85.875,73.25 U10.J1@86.65,73.25
MP257_WAKEUP: U10.P5 U26.32 | length 41.9
  Top Layer w0.09: v2@89.445,68.85 U10.P5@89.845,69.25
  Top Layer w0.15: v3(61.3,80.4) 61.3,79.653 61.4,79.553 U26.32@61.4,78.97
  Bottom Layer w0.09: 78.3,72.05 79.4,70.95 82.9,70.95 83.945,69.905 84.158,69.905 84.747,69.316 84.982,69.316 85.763,68.535 87.46,68.535 87.6,68.675 v2(89.45,68.675)
  Bottom Layer w0.1: v3(61.3,80.4) 61.881,80.4 62.3,80.819 62.3,81.657 63.418,82.775 74.895,82.775 78.295,79.375 78.295,72.05
NetB2_2: B2.2 C155.2 U26.1 | length 26.2
  Top Layer w0.15: B2.2@39.882,67.292 41.271,67.292 41.933,66.63 41.933,65.666 42.532,65.067 43.658,65.067 45.208,66.618 52.086,66.618 52.59,66.114 55.417,66.114 55.696,66.393 55.696,67.818 ; 55.7,67.825 55.847,67.972 56.054,67.972 C155.2@56.227,68.145 56.062,68.31 55.838,68.31 55.687,68.46 55.687,71.008 56.462,71.783 56.462,72.237 56.855,72.63 U26.1@57.4,72.63
NetC43_2: C43.2 U26.45 | length 6.7
  Top Layer w0.21: 56.275,77.6 U26.45@56.83,77.6
  Top Layer w0.25: C43.2@50.515,76.79 53.231,76.79 53.676,77.235 53.951,77.235 54.316,77.6 56.275,77.6
NetC81_1: C81.1 R64.2 X1.1 | length 2.2
  Top Layer w0.1: X1.1@76.525,67.4 78.65,67.4 R64.2@78.7,67.45
NetC88_1: C88.1 CN12.2 | length 2.1
  Top Layer w0.3: C88.1@67.475,61.3 CN12.2@67.475,63.425
NetC88_2: C88.2 D6.2 R66.2 | length 8
  Top Layer w0.3: C88.2@67.475,60.4 67.475,59.726 67.651,59.55 68.675,59.55 ; R66.2@68.675,60.395 68.675,59.55 ; D6.2@70.625,63.075 70.625,60.025 70.15,59.55 68.675,59.55
NetC91_1: C91.1 U26.7 | length 6.1
  Top Layer w0.21: U26.7@59.8,72.63 59.8,71.025 60.215,70.61 60.215,70.253
  Top Layer w0.3: v3(59.74,67.58) C91.1@60.35,67.58 ; 60.215,70.253 60.215,70.118 60.835,69.498 60.835,69.035 60.35,68.55 C91.1@60.35,67.73
NetC92_1: C92.1 R3.1 X2.3 | length 1.9
  Top Layer w0.09: X2.3@75.573,60.801 75.573,59.877 75.548,59.852 75.55,59.85 76.35,59.85 R3.1@76.475,59.725
NetC182_2: C182.2 C481.2 U24.C2 | length 2.6
  Top Layer w0.09: U24.C2@108.275,87.85 108.525,87.6 v3(108.525,86.8)
  Bottom Layer w0.11: C182.2@107.825,86.8 v3(108.525,86.8) C481.2@109.2,86.8 C481.2@109.225,86.775
NetC208_1: C208.1 U26.8 | length 5.4
  Top Layer w0.21: U26.8@60.2,72.63 60.2,71.134 60.625,70.709 60.625,70.345 60.798,70.173
  Top Layer w0.3: 60.798,70.173 61.3,69.67 61.3,68.843 61.175,68.718 C208.1@61.175,67.705
NetC384_2: C384.2 U10.K6 | length 1
  Top Layer w0.09: v2@90.262,72.063 U10.K6@90.65,72.45
  Bottom Layer w0.2: v2(90.325,72.075) 90.363,72.037 90.363,71.775 90.463,71.675 C384.2@90.5,71.675
NetC407_2: C407.2 C409.2 C417.2 R199.2 U10.P15 U10.R15 U10.U14 | length 48.3
  Top Layer w0.1: U10.U14@97.05,66.85 97.225,66.85 v2(97.45,67.075) ; U10.R15@97.85,68.45 97.85,68.275 v2(98.25,67.875) ; U10.P15@97.85,69.25 97.85,69.075 v2(98.25,68.675)
  Top Layer w0.3: v2(73.725,62.15) 74.647,63.072 74.647,70.522 75.65,71.525 75.65,74.8 R199.2@75.5,74.95
  Signal Layer 2 w0.3: v2(73.725,62.15) 73.725,62.124 75.823,60.026 93.576,60.026 96.599,63.049 v4@97.289,63.049
  Bottom Layer w0.1: C407.2@97.8,65.6 97.8,66.763 97.488,67.075 v2(97.45,67.075) v2(98.25,67.875) 98.375,68 C417.2@98.375,68.25 ; v2(98.25,68.675) 98.375,68.55 C417.2@98.375,68.275
  Bottom Layer w0.3: v4(97.275,63.05) 97.275,65.31 97.54,65.575 97.775,65.575 C407.2@97.8,65.6 ; v2(98.25,68.675) 98.375,68.8 C409.2@98.375,69.05
NetC408_2: C408.2 R197.2 U10.R16 | length 3
  Top Layer w0.1: U10.R16@98.65,68.45 99.05,68.05 v2(99.05,67.875)
  Bottom Layer w0.1: v2(99.05,67.875) 99.35,67.575 99.35,67.5 C408.2@99.45,67.4 ; C408.2@99.475,67.375 99.35,67.25 99.319,67.25 99.1,67.031 99.1,66.575 R197.2@99.525,66.15
NetCN12_1: CN12.1 R66.1 | length 4.4
  Top Layer w0.3: CN12.1@67.475,64.675 68.344,64.675 68.675,64.344 R66.1@68.675,61.295
NetD5_1: D5.1 R248.1 U24.K5 | length 9.2
  Top Layer w0.18: v3(111.225,89.9) U24.K5@111.775,89.35
  Bottom Layer w0.1: D5.1@104.175,88.63 D5.1@104.25,88.63 ; D5.1@104.25,88.6 106.625,90.975 R248.1@107.85,90.975 110.175,90.975 v3@111.2,89.95
NetD6_1: D6.1 R67.1 | length 1.4
  Top Layer w0.3: D6.1@70.625,64.975 R67.1@70.625,66.375
NetL1_1: L1.1 U26.37 | length 4.2
  Top Layer w0.21: U26.37@59.4,78.97 59.4,79.525
  Top Layer w0.25: L1.1@59.2,83.135 59.2,80.173 59.4,79.973 59.4,79.525
NetL2_1: L2.1 U26.26 | length 4.1
  Top Layer w0.2: U26.26@63.417,77.6 63.9,77.6 64.225,77.925 64.225,80.56 ; L2.1@65.35,81.685 L2.1@65.35,82.2
NetL3_1: L3.1 U26.40 | length 5.9
  Top Layer w0.15: L3.1@53.198,80.162 L3.1@53.35,80.01
  Top Layer w0.21: L3.1@53.35,80.275 53.635,79.99 55.41,79.99 57.765,79.99 58.2,79.555 U26.40@58.2,78.97
NetL4_1: L4.1 U26.23 | length 3.8
  Top Layer w0.15: L4.1@66.86,75.885 L4.1@66.86,76.4
  Top Layer w0.21: U26.23@63.17,76.4 63.725,76.4
  Top Layer w0.25: 63.725,76.4 66.5,76.4
NetL5_1: L5.1 U26.48 | length 7.2
  Top Layer w0.15: L5.1@51.118,74.448 L5.1@51.37,74.7 ; L5.1@51.59,74.585 L5.1@51.59,75.1
  Top Layer w0.21: 56.275,76.4 U26.48@56.83,76.4
  Top Layer w0.25: 51.325,75.6 51.775,76.05 54.7,76.05 55.05,76.4 56.275,76.4 ; L5.1@51.59,75.1 51.59,75.615
NetL6_1: L6.1 U26.19 | length 4.9
  Top Layer w0.21: U26.19@63.17,74.8 63.725,74.8
  Top Layer w0.25: 63.725,74.8 64.123,74.8 64.298,74.625 64.65,74.625 64.875,74.4 64.875,73.325 65.571,72.629 65.925,72.629 65.93,72.624 L6.1@65.93,72.025
NetL7_1: L7.1 U26.51 | length 7.4
  Top Layer w0.21: 56.275,75.2 U26.51@56.83,75.2
  Top Layer w0.25: L7.1@53.925,70.425 L7.1@53.925,70.669 ; L7.1@53.975,69.95 54.375,70.35 54.375,72.184 54.85,72.659 54.85,74.503 55.547,75.2 56.275,75.2
NetLD11_1: LD11.1 R210.2 | length 1
  Top Layer w0.2: LD11.1@42.887,68.077 R210.2@42.887,69.07
NetR2_2: R2.2 U26.56 | length 6.1
  Top Layer w0.15: R2.2@55.08,68.145 55.08,68.76 55.375,69.055 55.375,71.091 56.012,71.728 56.012,72.985 56.227,73.2 U26.56@56.755,73.2
NetR46_2: R46.2 U26.30 | length 2.8
  Top Layer w0.15: U26.30@62.2,78.97 62.2,80.87 62.532,81.202 62.532,81.43 R46.2@62.65,81.548
NetR57_2: R57.2 U26.12 | length 4.9
  Top Layer w0.21: U26.12@61.8,72.63 61.8,72.016 61.97,71.845
  Top Layer w0.3: 61.97,71.845 62.525,71.291 62.525,70.174 63.35,69.349 R57.2@63.35,68.4
NetR59_2: R59.2 U26.54 | length 8.5
  Top Layer w0.15: R59.2@52.98,68.145 52.98,68.64 53.15,68.81 54.236,68.81 54.875,69.449 54.875,71.298 55.512,71.935 55.512,73.335 56.177,74 U26.54@56.83,74
NetR60_2: R60.2 U26.55 | length 7.1
  Top Layer w0.15: R60.2@54.03,68.145 54.104,68.145 55.125,69.166 55.125,71.194 55.762,71.832 55.762,73.232 56.131,73.6 U26.55@56.83,73.6
NetR81_2: R81.2 U26.31 | length 5.7
  Top Layer w0.15: U26.31@61.8,78.97 61.8,80.973 61.95,81.123 61.95,83.81 62.038,83.898 R81.2@62.663,83.898
NetR94_1: R94.1 U2.A5 | length 1.5
  Top Layer w0.2: v2(105.675,71.69) 105.729,71.69 105.763,71.656 105.767,71.652 106.123,71.652 U2.A5@106.125,71.65
  Top Layer w0.22: v2(105.675,71.69) 105.709,71.656 105.763,71.656 U2.A5@106.085,71.656
  Bottom Layer w0.09: R94.1@105.5,72.25 105.5,71.875 v2@105.675,71.7
NetR112_2: R112.2 U10.G16 | length 0.9
  Top Layer w0.1: U10.G16@98.65,74.85 98.65,74.89 v4@99.028,75.268
  Bottom Layer w0.1: R112.2@99.025,74.875 v4(99.025,75.25)
NetR161_1: R161.1 U10.C7 | length 2
  Top Layer w0.1: v4@91.05,78.55 v4(91.05,78.525) 91.05,78.45 U10.C7@91.45,78.05
  Bottom Layer w0.1: R161.1@90.6,79.65 90.6,79 v4@91.05,78.55
NetR162_1: R162.1 U10.C3 | length 4.7
  Top Layer w0.09: R162.1@85.15,80.2 85.289,80.339 86.531,80.339 86.761,80.109 86.761,79.956 86.945,79.772 86.945,78.904 87.294,78.555 87.572,78.555 87.582,78.565 87.735,78.565 U10.C3@88.25,78.05
NetR196_2: R196.2 U10.T14 | length 4.2
  Top Layer w0.1: R196.2@96.55,63.625 96.55,67.15 U10.T14@97.05,67.65
NetTP9_1: TP9.1 U24.H5 | length 3.9
  Top Layer w0.09: 110.525,87.025 110.525,88.468 110.775,88.718 U24.H5@110.775,89.35
  Top Layer w0.11: TP9.1@109.5,86 110.525,87.025
NJTRST: U10.U2 | length 2.9
  Top Layer w0.09: 85.277,65.1 86.522,66.345 86.772,66.345 86.788,66.329 86.863,66.329 87.306,66.771 87.314,66.771 87.393,66.85 U10.U2@87.45,66.85
NRST: C33.2 R81.1 U10.N1 | length 48.8
  Top Layer w0.09: 81.733,66.05 83.863,68.18
  Top Layer w0.1: v2@75.425,70.347 C33.2@75.425,69.775 75.4,69.775 75.195,69.57 75.195,69.544 74.971,69.32 74.971,64.793 75.534,64.23 79.62,64.23 81.44,66.05 81.733,66.05 ; 83.863,68.18 83.863,68.218 85.45,69.805 85.927,69.805 86.15,70.028 86.628,70.028 U10.N1@86.65,70.05
  Top Layer w0.15: v2(61.604,84.33) 62.072,84.798 R81.1@62.663,84.798
  Bottom Layer w0.1: v2(61.604,84.33) 61.139,84.33 59.159,82.35 59.159,80.601 61.914,77.847 68.567,77.847 71.354,75.06 74.014,75.06 75.433,73.641 75.433,70.356 v2(75.424,70.347)
NRSTC1MS: D5.2 R27.1 R59.1 R272.1 U10.P2 | length 136.7
  Top Layer w0.1: R59.1@52.98,67.245 53.075,67.245 53.28,67.04 53.28,66.773 53.338,66.715 53.368,66.686 53.368,66.398 53.309,66.339 52.683,66.339 52.179,66.843 45.115,66.843 43.565,65.292 43.304,65.292 43.275,65.322 43.246,65.351 43.246,65.392 43.246,65.42 ccw(c42.887,65.648) 43.248,65.871 43.248,65.94 43.277,65.969 43.427,66.119 43.427,67.035 43.345,67.117 42.43,67.117 42.347,67.035 42.347,66.119 42.459,66.007 42.464,65.736 42.464,65.69 ccw(c42.887,65.648) 42.462,65.651 42.406,65.595 42.323,65.595 42.158,65.759 42.158,66.724 41.365,67.517 40.789,67.517 40.73,67.576 40.73,68.053 40.648,68.135 39.032,68.135 38.95,68.053 38.95,66.537 39.032,66.455 40.648,66.455 40.73,66.537 40.73,67.009 40.789,67.067 41.178,67.067 41.708,66.537 41.708,65.573 42.439,64.842 43.751,64.842 45.302,66.393 51.993,66.393 52.496,65.889 53.134,65.889 53.193,65.831 v1(53.193,65.664) ; v2(77.77,73.043) 80.231,75.504 v2(80.231,95.106) ; v4(85.316,68.476) 85.411,68.57 86.042,68.57 86.421,68.95 86.774,68.95 87.068,69.244 87.444,69.244 U10.P2@87.45,69.25
  Bottom Layer w0.1: v1(53.193,65.664) 53.193,66.452 53.682,66.942 53.682,66.945 53.708,66.971 53.833,67.095 53.997,67.095 56.529,67.172 56.612,67.172 56.641,67.143 57.799,65.986 72.361,65.986 72.425,66.05 75.524,66.05 78.443,68.969 ; v2(77.77,73.043) 77.77,69.642 78.443,68.969 ; v2(80.231,95.106) 83.075,97.95 99.821,97.95 104.175,93.596 D5.2@104.175,90.77 ; v4(85.316,68.476) v4@85.15,68.476 ; R272.1@85.925,67.95 85.744,68.131 85.489,68.131 85.373,68.246 85.373,68.337 85.336,68.375 85.245,68.375 85.245,68.408 85.178,68.476 v4@85.15,68.476 ; 78.443,68.969 78.449,68.975 81.975,68.975 84.826,68.975 85.15,68.651 v4@85.15,68.476
OSC32_IN: C86.1 U10.M2 X1.2 | length 14.4
  Top Layer w0.1: X1.2@76.525,65.9 C86.1@77.85,65.9 77.85,66.725 78,66.875 79.843,66.875 80.005,67.038 80.005,68.598 80.383,68.975 82.833,68.975 83.898,70.04 84.455,70.04 84.965,70.55 86.793,70.55 87.093,70.85 U10.M2@87.445,70.85
OSC32_OUT: R64.1 U10.M1 | length 9.1
  Top Layer w0.09: 84.982,70.85 U10.M1@86.65,70.85
  Top Layer w0.1: R64.1@79.6,67.45 79.6,68.475 80.3,69.175 82.75,69.175 83.815,70.24 84.372,70.24 84.982,70.85
PA1: U10.P14 | length 3.8
  Top Layer w0.1: U10.P14@97.05,69.25 97.082,69.218 97.082,69.068 v2(97.325,68.825)
  Bottom Layer w0.1: 96.84,65.801 96.84,68.34 v2(97.325,68.825)
PA2: U10.T10 | length 1.1
  Top Layer w0.09: v2@93.445,67.25 U10.T10@93.845,67.65
  Bottom Layer w0.09: 93.445,66.562 v2@93.445,67.075
  other v2: 93.45,67.075
PA3: U10.U12 | length 3
  Top Layer w0.09: 94.95,64.046 94.95,65.955 95.145,66.15 95.145,66.55 U10.U12@95.445,66.85
PA4: U10.T13 | length 1.1
  Top Layer w0.09: v2(95.85,67.075) 96.226,67.451 96.226,67.631 U10.T13@96.245,67.65
  Bottom Layer w0.09: 95.849,66.699 v2@95.849,67.074
PA5: U10.T11 | length 1.3
  Top Layer w0.09: v2(94.35,67.2) 94.61,67.46 94.61,67.615 U10.T11@94.645,67.65
  Bottom Layer w0.09: 94.25,66.563 94.35,66.663 v2(94.35,67.2)
PA6: U10.P11 | length 2.8
  Top Layer w0.09: v2@94.245,68.85 U10.P11@94.645,69.25
  Bottom Layer w0.09: v2(94.25,68.675) 94.7,68.225 94.7,66.66
PA7: U10.P12 | length 3.8
  Top Layer w0.09: v2@95.049,68.774 95.049,68.812 95.445,69.207 U10.P12@95.445,69.25
  Bottom Layer w0.09: v2@95.05,68.669 95.408,68.31 95.903,68.31 96.393,67.819 96.393,66.308
  other v2: 95.05,68.675
PA8: U10.U13 | length 2.8
  Top Layer w0.09: 95.746,64.237 95.746,65.915 95.845,66.013 95.845,66.45 U10.U13@96.245,66.85
PA9: U10.V10 | length 1.1
  Top Layer w0.09: 93.555,65.087 93.555,65.76 U10.V10@93.845,66.05
PA10: U10.W10 | length 0.9
  Top Layer w0.09: 93.85,64.356 U10.W10@93.85,65.25
PA11: U10.R8 | length 1.1
  Top Layer w0.09: v2(91.85,67.875) 91.85,67.888 92.219,68.258 92.219,68.419 U10.R8@92.25,68.45
  Bottom Layer w0.09: 91.57,67.596 v2(91.85,67.875)
PA12: U10.R9 | length 1.7
  Top Layer w0.09: v2@92.652,67.873 93.028,68.249 93.028,68.428 U10.R9@93.05,68.45
  Bottom Layer w0.09: 92.283,67.042 92.283,67.5 v2@92.65,67.867
  other v2: 92.65,67.875
PA13: U10.P9 | length 3.1
  Top Layer w0.09: v2@92.664,68.774 92.664,68.821 93.043,69.201 93.045,69.201 U10.P9@93.045,69.25
  Bottom Layer w0.09: 91.45,66.839 91.45,67.183 91.742,67.475 91.938,67.475 92.195,67.732 92.195,68.018 92.19,68.023 92.19,68.212 v2@92.65,68.672
  other v2: 92.65,68.675
PA14: U10.P8 | length 2.9
  Top Layer w0.09: v2(91.85,68.675) 91.85,68.743 92.053,68.946 92.053,69.01 92.245,69.202 U10.P8@92.245,69.25
  Bottom Layer w0.09: 91.029,66.851 91.029,67.365 91.395,67.731 91.395,68.018 91.392,68.021 91.392,68.224 v2@91.843,68.675
PA15: U10.U9 | length 1.8
  Top Layer w0.09: 92.56,65.265 92.56,65.451 92.645,65.536 92.645,66.45 U10.U9@93.045,66.85
PB0: U10.A9 | length 0.6
  Top Layer w0.1: U10.A9@93.05,79.65 93.05,80.281
PB1: U10.C8 | length 2.5
  Top Layer w0.1: 91.95,80.172 91.95,79.526 92.326,79.15 92.374,79.15 92.55,78.974 92.55,78.35 U10.C8@92.25,78.05
PB2: U10.C9 | length 1.9
  Top Layer w0.1: 92.55,79.759 92.55,79.356 92.75,79.156 92.75,78.343 U10.C9@93.043,78.05
PB3: U10.E8 | length 4.1
  Top Layer w0.09: v2@91.904,76.951 91.964,76.892 91.964,76.731 U10.E8@92.245,76.45
  Bottom Layer w0.09: 89.2,78.575 89.813,78.575 90.705,77.683 90.705,77.507 90.962,77.25 91.45,77.25 v2(91.85,76.85)
PB4: U10.B10 | length 1
  Top Layer w0.1: 93.55,79.712 93.55,79.15 U10.B10@93.85,78.85
PB5: U10.A10 | length 0.5
  Top Layer w0.1: U10.A10@93.85,79.65 93.85,80.175
PB6: U10.B9 | length 1.2
  Top Layer w0.1: 92.75,79.974 92.75,79.526 93.05,79.226 U10.B9@93.05,78.85
PB7: U10.B8 | length 1.6
  Top Layer w0.1: 91.75,80.255 91.75,79.35 U10.B8@92.25,78.85
PB8: U10.D8 | length 3.7
  Top Layer w0.1: v2@91.845,77.65 U10.D8@92.245,77.25
  Bottom Layer w0.1: 89.55,79.547 90.7,78.397 90.7,78.38 90.993,78.087 91.107,78.087 91.4,77.795 91.4,77.709 91.459,77.65 v2(91.85,77.65)
PB9: U10.E7 | length 3.4
  Top Layer w0.09: v2@91.07,76.951 91.07,76.887 91.445,76.512 U10.E7@91.445,76.45
  Bottom Layer w0.09: 88.9,78.155 89.155,77.9 89.155,77.888 89.292,77.752 89.661,77.752 90.107,77.305 90.283,77.305 90.595,76.993 90.595,76.903 90.648,76.85 v2(91.05,76.85)
PB10: U10.A8 | length 0.6
  Top Layer w0.1: U10.A8@92.25,79.65 92.25,80.282
PB11: U10.D7 | length 2.8
  Top Layer w0.1: v4@91.025,77.65 v4(91.05,77.65) U10.D7@91.45,77.25
  Bottom Layer w0.1: 89.475,79.25 89.475,79.225 v4(91.05,77.65)
PB12: U10.B16 | length 1.2
  Top Layer w0.09: U10.B16@98.65,78.85 98.95,79.15 98.95,79.928
PB13: U10.C15 | length 1.9
  Top Layer w0.09: U10.C15@97.845,78.05 97.845,78.395 98.355,78.905 98.355,79.76
PB14: U10.E16 | length 1.9
  Top Layer w0.1: U10.E16@98.65,76.45 98.65,76.473 99.005,76.828 v2@99.005,76.85
  Bottom Layer w0.1: v2@99.005,76.85 99.062,76.907 99.062,77.157 99.408,77.503 99.408,78.078
  other v2: 99,76.85
PB15: U10.W3 | length 0.6
  Top Layer w0.09: 88.245,64.7 88.245,65.245 U10.W3@88.25,65.25
PC0: U10.P10 | length 2.9
  Top Layer w0.09: v2@93.428,68.775 93.428,68.804 93.845,69.221 U10.P10@93.845,69.25
  Bottom Layer w0.09: 93,66.609 93,68.215 93.45,68.665 v2(93.45,68.675)
PC1: U10.V9 | length 1
  Top Layer w0.09: 92.75,65.128 92.75,65.372 93.045,65.667 U10.V9@93.045,66.05
PC2: U10.V8 | length 1.1
  Top Layer w0.09: 91.945,65.05 91.945,65.75 U10.V8@92.245,66.05
PC3: U10.V5 | length 1.4
  Top Layer w0.09: 89.349,64.884 89.349,65.555 U10.V5@89.845,66.05
PC4: U10.T6 | length 1.1
  Top Layer w0.09: v2@90.283,67.201 90.283,67.242 90.645,67.603 U10.T6@90.645,67.65
  Bottom Layer w0.09: 90.25,66.569 v2(90.25,67.075)
PC5: U10.R7 | length 1.9
  Top Layer w0.09: v2(91.05,67.875) 91.426,68.251 91.426,68.426 U10.R7@91.45,68.45
  Bottom Layer w0.09: 90.633,66.839 90.633,67.453 v2@91.05,67.869
PC6: U10.T7 | length 3.7
  Top Layer w0.09: 90.165,64.471 90.165,65.532 90.344,65.711 90.344,66.17 90.518,66.345 90.562,66.345 91.084,66.867 91.084,67.243 91.445,67.603 U10.T7@91.445,67.65
PC7: U10.U6 | length 2.1
  Top Layer w0.09: 89.555,65.2 89.555,65.372 89.938,65.755 89.972,65.755 90.145,65.928 90.145,66.373 90.623,66.85 U10.U6@90.65,66.85
PC8: U10.V6 | length 1.1
  Top Layer w0.09: 90.355,65.038 90.355,65.389 90.65,65.684 U10.V6@90.65,66.05
PC9: U10.W6 | length 1.1
  Top Layer w0.09: 90.65,64.191 U10.W6@90.65,65.25
PC10: U10.U7 | length 2.7
  Top Layer w0.09: 90.96,64.366 90.96,66.03 91.45,66.521 U10.U7@91.45,66.85
PC11: U10.U5 | length 1.2
  Top Layer w0.09: v4(89.45,66.275) 89.826,66.651 89.826,66.826 U10.U5@89.85,66.85
  Bottom Layer w0.09: 89.448,65.866 89.45,65.868 v4(89.45,66.275)
PC12: U10.V4 | length 1.1
  Top Layer w0.09: 88.755,65.095 88.755,65.372 88.928,65.545 88.997,65.545 89.05,65.598 U10.V4@89.05,66.05
PCIE_CLKINN: U10.W13 | length 0.8
  Top Layer w0.1: 96.25,64.45 U10.W13@96.25,65.25
PCIE_CLKINP: U10.V13 | length 1.8
  Top Layer w0.09: 95.955,64.334 95.955,65.372 96.036,65.453 96.036,65.841 U10.V13@96.245,66.05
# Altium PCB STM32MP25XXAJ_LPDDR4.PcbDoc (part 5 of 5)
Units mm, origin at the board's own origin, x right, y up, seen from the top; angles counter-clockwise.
Board outline 172 x 137 mm, 4 copper layers (Top Layer, Signal Layer 1, Signal Layer 2, Bottom Layer), stack 1.614 mm thick; 188 components, 294 nets, 1141 pads, 872 vias.
Unrouted connection lines stored in the file: 13.

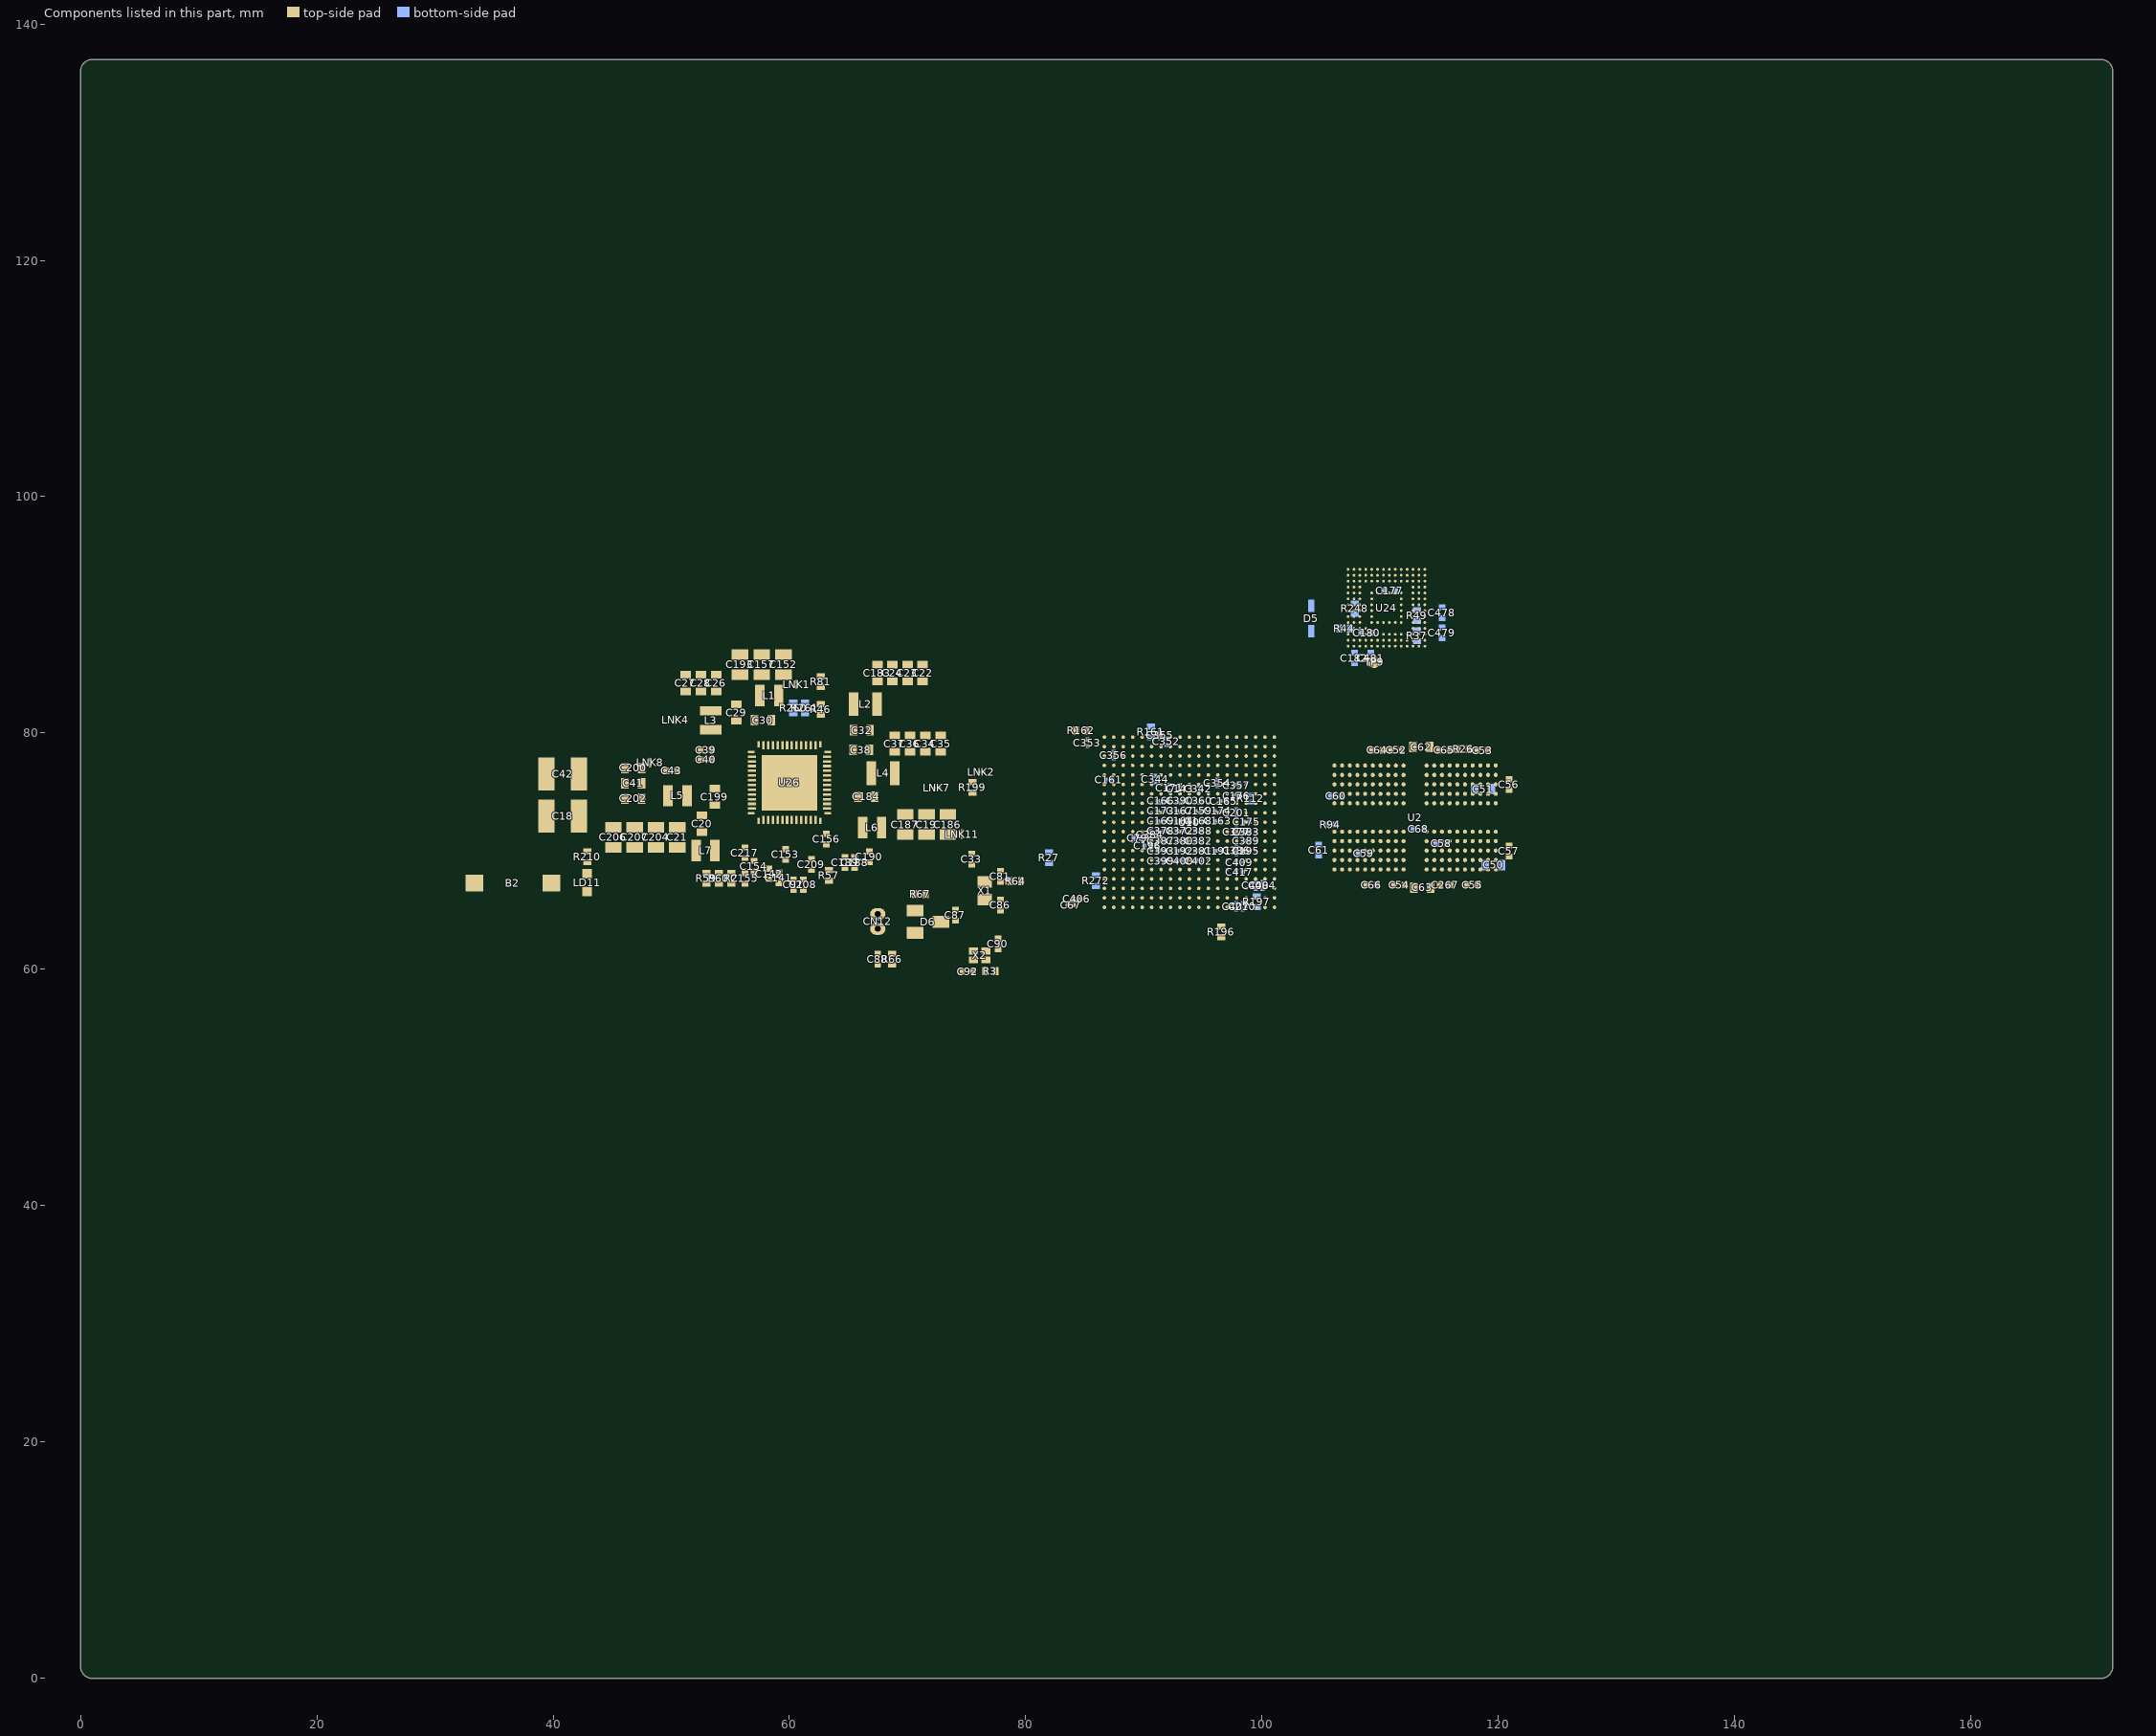
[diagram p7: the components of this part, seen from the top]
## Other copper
Top Layer:
  rectangle net VDD2_DDR: 47.155,73.8 50.125,75.6
  region net 5V_STLK: 56.73,80.524 56.631,80.425 56.275,80.425 cw(c56.275,80.775) 55.925,80.775 55.925,80.825 55.2,80.825 ccw(c55.2,80.75) 55.125,80.75 55.125,80.4 ccw(c55.327,80.397) 55.325,80.195 57.95,80.195 58.35,79.8 58.612,79.8 57.891,80.521 57.625,80.525
  region net 5V_STLK: 65.105,79.78 64.93,79.672 ccw(c65.063,79.473) 64.894,79.642 64.853,79.601 ccw(c65.113,79.342) 64.746,79.342 64.746,79.326 ccw(c65.101,79.326) 64.85,79.075 64.85,77.539 64.849,77.538 64.847,77.551 64.376,77.08 63.77,77.08 63.77,77.345 64.006,77.345 64.48,77.819 64.48,80.347 64.808,80.67 65.825,80.67 65.825,79.78
  region net GND: 56.4,79.685 56.307,79.685 ccw(c56.307,79.584) 56.235,79.655 55.955,79.375 ccw(c56.026,79.303) 55.925,79.303 55.925,78.975 56.425,78.975 cw(c56.823,78.982) 56.815,79.38 57.075,79.375 ccw(c57.075,79.423) 57.109,79.389 57.205,79.485
  region net GND: 63.725,76 63.65,75.925 63.572,75.925 cw(c63.572,75.798) 63.662,75.888 63.688,75.862 ccw(c63.778,75.952) 63.778,75.825 64.447,75.825 cw(c64.447,75.698) 64.537,75.788 64.6,75.725 64.729,75.854 cw(c64.78,75.803) 64.78,75.875
  region net NetL1_1: 59.072,81.875 ccw(c58.769,81.883) 58.978,82.102 58.955,82.125 58.955,82.187 59.026,82.194 ccw(c59.025,82.194) 59.025,82.195 59.175,82.075
  pour cut-out: 96.425,80.35 96.425,83.15 100.15,86.875 100.15,91.2 101.7,92.75 105.575,92.75 108.7,89.625 111.95,89.625 113.15,88.425 113.15,86.8 109.95,83.6 105.175,83.6 101.925,80.35
  pour cut-out: 99.202,80.825 112.025,80.825 112.025,63.875 99.075,63.875
  pour cut-out: 85.462,80.05 100.737,80.05 100.737,64.85 85.312,64.85
  region net 5V_STLK: 65.695,78.175 65.695,77.32 65.625,77.25 65.5,77.375 64.9,77.375 65.055,77.53 65.055,78.175
  region net 5V_STLK: 65.625,77.25 65.05,76.675 64.375,76.675 64.375,76.85 64.9,77.375
  region net 5V_STLK: 54.375,72.9 54.216,72.9 54.189,72.874 54.148,72.842 54.102,72.815 54.054,72.795 54.003,72.782 53.951,72.775 53.925,72.774 53.425,72.774 53.399,72.775 53.347,72.782 53.296,72.795 53.248,72.815 53.202,72.842 53.161,72.874 53.15,72.45 53.15,71.945 52.875,71.945 52.875,71.305 53.33,71.305 54.099,72.074 54.099,72.184 54.103,72.227 54.113,72.27 54.129,72.31 54.152,72.346 54.18,72.379 54.538,72.737
  region net 5V_STLK: 51.575,71.948 52.225,71.948 52.225,71.305 51.92,71.305 51.825,71.4 51.575,71.4
  region net 5V_STLK: 54.75,75.62 54.75,75.4 54.33,74.98 52.65,74.98 52.65,75.525 52.9,75.525 52.995,75.62
  region net 5V_STLK: 65.575,73.875 65.575,74.125 64.675,75.025 65.425,75.025 65.747,74.703
  region net 5V_STLK: 65.575,73.85 65.477,73.948 65.477,74.625 66.12,74.625 66.12,73.895 66.075,73.85 66.075,73.6 65.575,73.6
  region net 5V_STLK: 58.675,81.85 58.77,81.755 58.77,81.45 58.13,81.45 58.13,81.805 58.175,81.85 58.175,82.1 58.675,82.1
  region net 5V_STLK: 58.925,79.725 58.9,79.725 58.13,80.495 58.13,80.825 58.77,80.825 58.77,80.605 58.9,80.475 58.9,79.925
  region net 5V_STLK: 65.675,81 65.825,80.85 65.825,80.6 65.025,80.6 65.025,80.85 65.175,81 65.175,81.25 65.675,81.25
  region net 5V_STLK: 65.625,79.35 65.775,79.2 65.775,78.95 64.975,78.95 64.975,79.2 65.125,79.35 65.125,79.6 65.625,79.6
  region net 5V_STLK: 54.75,81.3 54.795,81.345 55.15,81.345 55.15,80.65 54.9,80.65 54.75,80.8 54.5,80.8 54.5,81.3
  region net GND: 51.575,72.75 51.62,72.705 52.18,72.705 52.225,72.75 52.225,73.345 51.92,73.345 51.825,73.25 51.575,73.25
  region net GND: 50.525,72.798 50.675,72.648 50.675,72.398 49.8,72.398 49.8,72.823 50.025,73.048 50.525,73.048
  region net GND: 50.525,72.798 50.375,72.648 50.375,72.398 51.2,72.398 51.2,72.873 51.025,73.048 50.525,73.048
  region net GND: 72.3,73.298 72.3,74.651 70.9,74.651 70.9,73.298
  region net GND: 59.525,87.425 59.675,87.275 59.675,87.025 58.8,87.025 58.8,87.45 59.025,87.675 59.525,87.675
  region net GND: 59.525,87.425 59.375,87.275 59.375,87.025 60.2,87.025 60.2,87.5 60.025,87.675 59.525,87.675
  region net GND: 57.675,87.425 57.825,87.275 57.825,87.025 56.95,87.025 56.95,87.45 57.175,87.675 57.675,87.675
  region net GND: 57.675,87.425 57.525,87.275 57.525,87.025 58.35,87.025 58.35,87.5 58.175,87.675 57.675,87.675
  region net GND: 56.1,81.323 56.297,81.52 56.75,81.52 56.75,80.63 56.293,80.63 56.1,80.823
  region net GND: 45.125,72.798 44.975,72.648 44.975,72.398 45.8,72.398 45.8,72.873 45.625,73.048 45.125,73.048
  region net GND: 45.125,72.798 45.275,72.648 45.275,72.398 44.4,72.398 44.4,72.823 44.625,73.048 45.125,73.048
  region net GND: 46.925,72.798 46.775,72.648 46.775,72.398 47.6,72.398 47.6,72.873 47.425,73.048 46.925,73.048
  region net GND: 46.925,72.798 47.075,72.648 47.075,72.398 46.2,72.398 46.2,72.823 46.425,73.048 46.925,73.048
  region net GND: 45.1,74.7 45.295,74.895 46.075,74.895 46.075,74.005 45.295,74.005 45.1,74.2
  region net GND: 48.725,72.798 48.575,72.648 48.575,72.398 49.4,72.398 49.4,72.873 49.225,73.048 48.725,73.048
  region net GND: 48.725,72.798 48.875,72.648 48.875,72.398 48,72.398 48,72.823 48.225,73.048 48.725,73.048
  region net GND: 57.075,79.375 56.74,79.375 56.74,79.385
  region net GND: 63.421,78.656 63.52,78.656 63.549,78.653 63.578,78.644 63.604,78.63 63.627,78.612 63.645,78.589 63.67,78.555 63.67,78.23 63.77,78.23 63.77,78.93 63.421,78.93
  region net GND: 53.425,72.952 53.23,73.147 53.23,73.602 54.12,73.602 54.12,73.147 53.925,72.952
  region net GND: 64.33,76.125 64.78,76.125 64.78,75.825 64.655,75.7 64.48,75.875 64.33,75.875
  region net GND: 45.1,77.3 45.295,77.495 46.075,77.495 46.075,76.605 45.295,76.605 45.1,76.8
  region net GND: 45.1,76 45.295,76.195 46.075,76.195 46.075,75.305 45.295,75.305 45.1,75.5
  region net GND: 51.45,85.873 51.645,85.678 51.645,85.223 50.755,85.223 50.755,85.678 50.95,85.873
  region net GND: 52.75,85.873 52.945,85.678 52.945,85.223 52.055,85.223 52.055,85.678 52.25,85.873
  region net GND: 54.05,85.873 54.245,85.678 54.245,85.223 53.355,85.223 53.355,85.678 53.55,85.873
  region net GND: 55.775,83.373 55.97,83.178 55.97,82.723 55.08,82.723 55.08,83.178 55.275,83.373
  region net GND: 55.825,87.425 55.675,87.275 55.675,87.025 56.5,87.025 56.5,87.5 56.325,87.675 55.825,87.675
  region net GND: 55.825,87.425 55.975,87.275 55.975,87.025 55.1,87.025 55.1,87.45 55.325,87.675 55.825,87.675
  region net GND: 70.45,80.825 70.645,80.63 70.645,79.775 69.755,79.775 69.755,80.63 69.95,80.825
  region net GND: 69.15,80.825 69.345,80.63 69.345,79.775 68.455,79.775 68.455,80.63 68.65,80.825
  region net GND: 67.7,86.825 67.895,86.63 67.895,85.775 67.005,85.775 67.005,86.63 67.2,86.825
  region net GND: 74.1,73.298 74.1,74.651 72.7,74.651 72.7,73.298
  region net GND: 70.5,73.298 70.5,74.651 69.1,74.651 69.1,73.298
  region net GND: 73.05,80.825 73.245,80.63 73.245,79.775 72.355,79.775 72.355,80.63 72.55,80.825
  region net GND: 71.75,80.825 71.945,80.63 71.945,79.775 71.055,79.775 71.055,80.63 71.25,80.825
  region net GND: 68.975,86.825 69.17,86.63 69.17,85.775 68.28,85.775 68.28,86.63 68.475,86.825
  region net GND: 70.25,86.825 70.445,86.63 70.445,85.775 69.555,85.775 69.555,86.63 69.75,86.825
  region net GND: 71.525,86.825 71.72,86.63 71.72,85.775 70.83,85.775 70.83,86.63 71.025,86.825
  region net GND: 67.8,78.325 67.605,78.13 66.75,78.13 66.75,79.02 67.605,79.02 67.8,78.825
  region net GND: 67.825,79.975 67.63,79.78 66.775,79.78 66.775,80.67 67.63,80.67 67.825,80.475
  region net GND: 68.002,74.375 67.807,74.18 67.5,74.18 67.5,75.07 67.975,75.07 68.17,74.875 68.17,74.375
  region net VDD2_DDR: 47.795,77.615 47.795,77.731 48.148,78.084 48.148,79.215 47.795,79.215 47.155,79.215 46.798,79.215 46.798,78.019 47.155,77.662 47.155,77.238 47.795,77.238
  region net VDDIO: 73.08,70.835 73.08,70.719 72.727,70.366 72.727,69.235 73.08,69.235 73.72,69.235 74.077,69.235 74.077,70.431 73.72,70.788 73.72,71.212 73.08,71.212
  pour cut-out: 74.825,62.125 78.033,62.125 78.26,62.125 78.785,61.6 78.785,59.714 78.283,59.211 74.825,59.211
  pour cut-out: 68.455,77.45 67.395,77.45 67.395,75.35 68.455,75.35
  pour cut-out: 74.1,71.925 69.13,71.925 69.13,72.575 74.1,72.575
  pour cut-out: 67.4,73.075 66.6,73.075 66.6,70.975 67.4,70.975
  pour cut-out: 67.355,72.875 69.13,72.875 69.13,71.6 67.8,71.6
  pour cut-out: 52.3,81.605 52.3,80.545 54.4,80.545 54.4,81.605
  pour cut-out: 66.945,83.25 65.885,83.25 65.885,81.15 66.945,81.15
  region net NetL1_1: 59.495,82.275 59.15,81.93 58.695,82.385 58.695,84.075 59.495,84.075
  pour cut-out: 58.655,84.225 57.935,84.225 57.935,82.125 58.655,82.125
  region net NetL2_1: 65.15,82.225 65.15,81.45 65.015,81.45 64.325,80.76 64.325,78 63.85,77.525 63.525,77.525 63.525,77.675 63.614,77.675 63.77,77.831 63.95,78.011 64.005,78.094 64.025,78.191 64.025,78.742 64.07,78.85 64.07,79.01 64.009,79.157 63.897,79.269 63.77,79.322 63.75,79.325 63.75,83.102 64.098,83.45 65.015,83.45 65.15,83.315 65.15,83.2
  region net NetL5_1: 50.925,75.948 51.15,76.173 52.525,76.173 52.525,74.323 52.002,73.8 51.725,73.8 50.925,73.8
  pour cut-out: 49.995,73.65 51.055,73.65 51.055,75.75 49.995,75.75
  region net NetL4_1: 66.025,77.6 66.025,75.6 66.934,75.6 66.934,77.6
  region net NetL7_1: 54.375,70.35 54.075,70.05 53.3,70.05 53.3,70.95 54.375,72.02
  region net NetL3_1: 54.075,78.975 52.888,80.162 53.988,80.162 54.075,80.075 57.68,80.075 57.92,79.835 56.29,79.835 56.267,79.833 56.248,79.829 56.22,79.82 56.201,79.813 56.175,79.799 56.158,79.788 56.135,79.769 55.841,79.474 55.822,79.452 55.811,79.435 55.802,79.419 55.79,79.39 55.786,79.378 55.781,79.362 55.777,79.342 55.776,79.327 55.774,79.313 55.774,78.975
  region net NetL3_1: 55.283,80.045 55.254,80.048 55.225,80.057 55.151,80.089 55.125,80.103 55.103,80.122 55.047,80.18 55.028,80.203 55.014,80.229 54.988,80.294 54.981,80.316 54.958,80.347 54.933,80.367 54.897,80.391 54.851,80.4 54.075,80.4 54.075,79.263
  pour cut-out: 53,72.6 51.05,72.6 51.05,72.025 53,72.025
  pour cut-out: 44.4,70.773 51.05,70.773 51.05,71.573 44.4,71.573
  pour cut-out: 53.44,71.1 52.38,71.1 52.38,69 53.44,69
  pour cut-out: 78.275,68.05 80,68.05 80,67.025 79.8,66.825 78.28,66.825 78.28,65.25 75.75,65.25 75.75,68.05
  pour cut-out: 106.875,94 107.125,94.25 114,94.25 114.175,94.075 114.175,87.1 114,86.925 107.15,86.925 106.875,87.2
  text "1" at 134.025,133.811 h2
Signal Layer 1:
  text "2" at 135.309,133.811 h2
Signal Layer 2:
  text "5" at 140.661,133.833 h2
Bottom Layer:
  pour cut-out: 97.15,76.45 97.15,81.7 99.375,83.925 101.875,83.925 102.85,82.95 102.85,77.375 102,76.525
  pour cut-out: 113.4,78.574 113.4,67.475 99.275,67.475 99.275,78.574
  text "6" at 142.16,133.822 h2

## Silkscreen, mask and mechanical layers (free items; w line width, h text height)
Top Overlay:
  text "J" at 41.681,116.917 h15
  text "VBAT" at 63.012,59.791 h1.2
Top Solder:
  region: 133.736,135.455 133.736,133.455 142.486,133.455 142.486,135.455
Bottom Solder:
  region: 133.736,135.455 133.736,133.455 142.486,133.455 142.486,135.455
M1-Board Shape:
  lines w0.1: 1,137 ccw(c1,136) 0,136 0,95 0,1 ccw(c1,1) 1,0 171,0 ccw(c171,1) 172,1 172,136 ccw(c171,136) 171,137 ; 1,137 1,137 ; 1,137 171,137 ; 171,137 171,137
M2-Board Dimensions:
  lines w0.1: 1,137 ccw(c1,136) 0,136 0,1 ccw(c1,1) 1,0 171,0 ccw(c171,1) 172,1 172,136 ccw(c171,136) 171,137 ; 1,137 1,137 ; 1,137 171,137 ; 171,137 171,137
Drill Drawing:
  drawing of 183 lines, arcs and shapes, not listed
  text "PCB SPECIFICATIONS :" at 3.455,183.85 h3
  text "MINIMUN PARAMETERS" at 155.325,183.145 h3
  text "PCB : TYPE 3" at 194.663,183.121 h3
  text "A.   MATERIAL :" at 3.455,179.85 h3
  text "FR-4" at 41.955,179.85 h3
  text "TG-170" at 58.455,179.85 h3
  text "X  TG-150" at 76.705,179.85 h3
  text "TG-140" at 92.705,179.85 h3
  text "DEFAULT" at 155.325,177.645 h3
  text "ASPECT-RATIO, AXE Z :" at 194.663,177.621 h3
  text "B.   MATERIAL FAMILY :" at 3.455,176.85 h3
  text "N/A" at 41.955,176.85 h3
  text "C.   SOLDERMASK COLOR :" at 3.455,173.85 h3
  text "GREEN" at 41.955,173.85 h3
  text "X  BLUE" at 58.455,173.85 h3
  text "RED" at 76.705,173.85 h3
  text "BLACK" at 92.705,173.85 h3
  text "TRACKS : 0.100mm           / GAPS : 0.100mm" at 155.325,171.895 h3
  text "6 :1  to  8 :1 / LEVEL \"B\"" at 194.682,170.874 h3
  text "D.   SILKSCREEN COLOR :" at 3.455,170.85 h3
  text "X  WHITE" at 41.955,170.85 h3
  text "YELLOW" at 58.455,170.85 h3
  text "BLACK" at 76.705,170.85 h3
  text "E.   SURFACE FINISH :" at 3.455,167.85 h3
  text "X  ENIG" at 41.955,167.85 h3
  text "IMMERSION SILVER" at 58.455,167.85 h3
  text "IMMERSION TIN" at 92.705,167.85 h3
  text "BGA :" at 155.3,167.07 h3
  text "Layer" at 244.479,166.45 h2
  text "Name" at 252.853,166.45 h2
  text "Material" at 269.05,166.45 h2
  text "Thickness" at 283.604,166.45 h2
  text "Constant" at 295.559,166.45 h2
  text "HASL" at 41.955,164.85 h3
  text "HASL (PB-FREE)" at 58.455,164.85 h3
  text "GOLDEN FINGER" at 92.705,164.85 h3
  text "Top Overlay" at 252.853,162.45 h2
  text "F.   IMPEDANCE CONTROL :" at 3.455,161.85 h3
  text "NO" at 41.955,161.85 h3
  text "X  YES" at 58.455,161.85 h3
  text "TRACKS : 0.090mm           / GAPS : 0.090mm" at 155.3,161.32 h3
  text "G.   THROUGH VIA :" at 3.455,158.85 h3
  text "PLUG THE VIAS WHICH ARE COVERED WITH SOLDERMASK ONE OR TWO SIDE." at 41.955,158.85 h3
  text "Top Solder" at 252.853,158.45 h2
  text "Solder Resist" at 269.05,158.45 h2
  text "0.025mm" at 283.604,158.45 h2
  text "3.5" at 295.559,158.45 h2
  text "PLUG MATERIAL :" at 41.955,155.85 h3
  text "X  SOLDERMASK" at 67.455,155.85 h3
  text "NON-CONDUCTIVE EPOXY." at 92.705,155.85 h3
  text "1" at 244.479,154.45 h2
  text "Top Layer" at 252.853,154.45 h2
  text "0.037mm" at 283.604,154.45 h2
  text "H.   STACK-UP :" at 3.455,152.85 h3
  text "SEE LAYER STACK-UP SEQUENCE FOR OVERALL THICKNESS." at 41.955,152.85 h3
  text "Dielectric 1" at 252.853,150.45 h2
  text "0.070mm" at 283.604,150.45 h2
  text "3.8" at 295.559,150.45 h2
  text "2" at 244.478,146.45 h2
  text "Signal Layer 1" at 252.853,146.45 h2
  text "0.035mm" at 283.604,146.45 h2
  text "Dielectric 2" at 252.853,142.45 h2
  text "1.330mm" at 283.604,142.45 h2
  text "4.3" at 295.559,142.45 h2
  text "3" at 244.479,138.45 h2
  text "Signal Layer 2" at 252.853,138.45 h2
  text "0.035mm" at 283.604,138.45 h2
  text "Dielectric 3" at 252.853,134.45 h2
  text "0.070mm" at 283.604,134.45 h2
  text "3.8" at 295.559,134.45 h2
  text "4" at 244.479,130.45 h2
  text "Bottom Layer" at 252.853,130.45 h2
  text "0.037mm" at 283.604,130.45 h2
  text "Bottom Solder" at 252.853,126.45 h2
  text "Solder Resist" at 269.05,126.45 h2
  text "0.025mm" at 283.604,126.45 h2
  text "3.5" at 295.559,126.45 h2
  text "Bottom Overlay" at 252.853,122.45 h2
  text "Symbol" at 183.644,16.166 h2.4
  text "Count" at 193.043,16.166 h2.4
  text "Hole Size" at 202.8,16.166 h2.4
  text "Plated" at 221.077,16.166 h2.4
  text "Hole Type" at 229.328,16.166 h2.4
  text "Drill Layer Pair" at 241.34,16.166 h2.4
  text "Via/Pad" at 264.12,16.166 h2.4
  text "Pad Shape" at 273.963,16.166 h2.4
  text "Hole Length" at 286.82,16.166 h2.4
  text "523" at 193.043,12.023 h2
  text "0.200mm (7.87mil)" at 202.8,12.023 h2
  text "PTH" at 221.077,12.023 h2
  text "Round" at 229.328,12.023 h2
  text "Top Layer - Bottom Layer" at 241.34,12.023 h2
  text "Via" at 264.12,12.023 h2
  text "Rounded" at 273.963,12.023 h2
  text "-" at 286.82,12.023 h2
  text "D" at 182.856,11.769 h1.84
  text "349" at 193.043,7.88 h2
  text "0.350mm (13.78mil)" at 202.8,7.88 h2
  text "PTH" at 221.077,7.88 h2
  text "Round" at 229.328,7.88 h2
  text "Top Layer - Bottom Layer" at 241.34,7.88 h2
  text "Via" at 264.12,7.88 h2
  text "Rounded" at 273.963,7.88 h2
  text "-" at 286.82,7.88 h2
  text "F" at 182.856,7.626 h1.84
  text "2" at 193.043,3.737 h2
  text "0.500mm (19.69mil)" at 202.8,3.737 h2
  text "PTH" at 221.077,3.737 h2
  text "Round" at 229.328,3.737 h2
  text "Top Layer - Bottom Layer" at 241.34,3.737 h2
  text "Pad" at 264.12,3.737 h2
  text "Rounded" at 273.963,3.737 h2
  text "-" at 286.82,3.737 h2
  text "874 Total" at 193.043,-0.407 h2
